VERSION 5.8 ;
BUSBITCHARS "[]" ;
DIVIDERCHAR "/" ;
UNITS
    DATABASE MICRONS 1000 ;
END UNITS

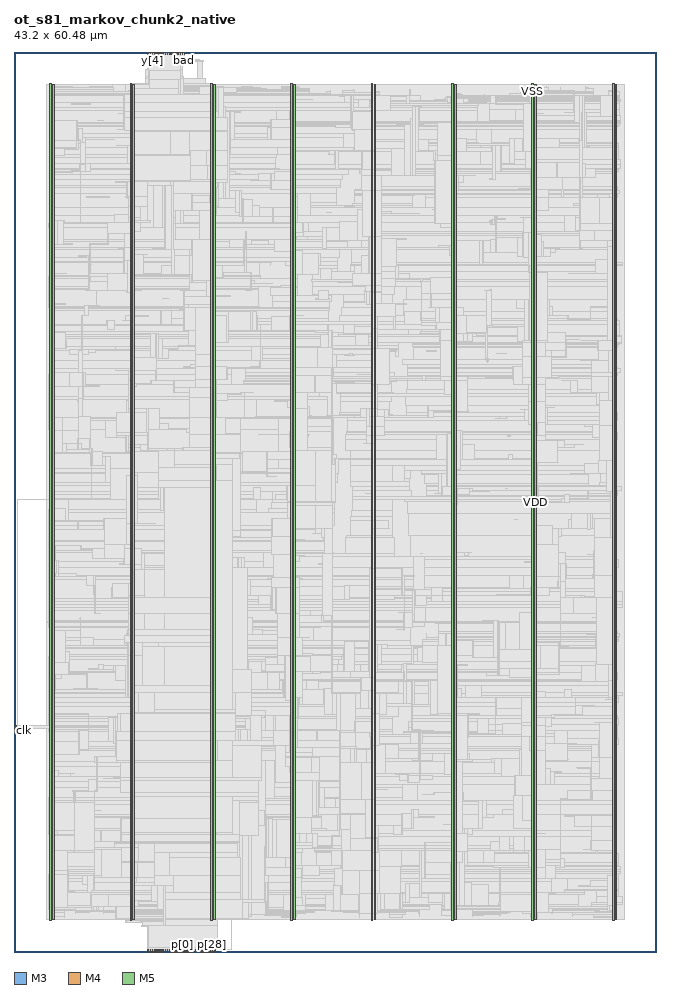
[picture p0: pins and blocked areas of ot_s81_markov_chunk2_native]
MACRO ot_s81_markov_chunk2_native
  FOREIGN ot_s81_markov_chunk2_native 0 0 ;
  CLASS BLOCK ;
  SIZE 43.2 BY 60.48 ;
  PIN bad
    DIRECTION OUTPUT ;
    USE SIGNAL ;
    PORT
      LAYER M3 ;
        RECT  11.448 60.336 11.466 60.48 ;
    END
  END bad
  PIN clk
    DIRECTION INPUT ;
    USE SIGNAL ;
    PORT
      LAYER M4 ;
        RECT  0 14.88 0.192 14.904 ;
    END
  END clk
  PIN p[0]
    DIRECTION INPUT ;
    USE SIGNAL ;
    PORT
      LAYER M3 ;
        RECT  11.304 0 11.322 0.144 ;
    END
  END p[0]
  PIN p[10]
    DIRECTION INPUT ;
    USE SIGNAL ;
    PORT
      LAYER M3 ;
        RECT  12.024 0 12.042 0.144 ;
    END
  END p[10]
  PIN p[11]
    DIRECTION INPUT ;
    USE SIGNAL ;
    PORT
      LAYER M5 ;
        RECT  12.048 0 12.072 0.192 ;
    END
  END p[11]
  PIN p[12]
    DIRECTION INPUT ;
    USE SIGNAL ;
    PORT
      LAYER M3 ;
        RECT  12.168 0 12.186 0.144 ;
    END
  END p[12]
  PIN p[13]
    DIRECTION INPUT ;
    USE SIGNAL ;
    PORT
      LAYER M5 ;
        RECT  12.192 0 12.216 0.192 ;
    END
  END p[13]
  PIN p[14]
    DIRECTION INPUT ;
    USE SIGNAL ;
    PORT
      LAYER M3 ;
        RECT  12.312 0 12.33 0.144 ;
    END
  END p[14]
  PIN p[15]
    DIRECTION INPUT ;
    USE SIGNAL ;
    PORT
      LAYER M5 ;
        RECT  12.336 0 12.36 0.192 ;
    END
  END p[15]
  PIN p[16]
    DIRECTION INPUT ;
    USE SIGNAL ;
    PORT
      LAYER M3 ;
        RECT  12.456 0 12.474 0.144 ;
    END
  END p[16]
  PIN p[17]
    DIRECTION INPUT ;
    USE SIGNAL ;
    PORT
      LAYER M5 ;
        RECT  12.48 0 12.504 0.192 ;
    END
  END p[17]
  PIN p[18]
    DIRECTION INPUT ;
    USE SIGNAL ;
    PORT
      LAYER M3 ;
        RECT  12.6 0 12.618 0.144 ;
    END
  END p[18]
  PIN p[19]
    DIRECTION INPUT ;
    USE SIGNAL ;
    PORT
      LAYER M5 ;
        RECT  12.624 0 12.648 0.192 ;
    END
  END p[19]
  PIN p[1]
    DIRECTION INPUT ;
    USE SIGNAL ;
    PORT
      LAYER M5 ;
        RECT  11.328 0 11.352 0.192 ;
    END
  END p[1]
  PIN p[20]
    DIRECTION INPUT ;
    USE SIGNAL ;
    PORT
      LAYER M3 ;
        RECT  12.744 0 12.762 0.144 ;
    END
  END p[20]
  PIN p[21]
    DIRECTION INPUT ;
    USE SIGNAL ;
    PORT
      LAYER M5 ;
        RECT  12.768 0 12.792 0.192 ;
    END
  END p[21]
  PIN p[22]
    DIRECTION INPUT ;
    USE SIGNAL ;
    PORT
      LAYER M3 ;
        RECT  12.888 0 12.906 0.144 ;
    END
  END p[22]
  PIN p[23]
    DIRECTION INPUT ;
    USE SIGNAL ;
    PORT
      LAYER M5 ;
        RECT  12.912 0 12.936 0.192 ;
    END
  END p[23]
  PIN p[24]
    DIRECTION INPUT ;
    USE SIGNAL ;
    PORT
      LAYER M3 ;
        RECT  13.032 0 13.05 0.144 ;
    END
  END p[24]
  PIN p[25]
    DIRECTION INPUT ;
    USE SIGNAL ;
    PORT
      LAYER M5 ;
        RECT  13.056 0 13.08 0.192 ;
    END
  END p[25]
  PIN p[26]
    DIRECTION INPUT ;
    USE SIGNAL ;
    PORT
      LAYER M3 ;
        RECT  13.176 0 13.194 0.144 ;
    END
  END p[26]
  PIN p[27]
    DIRECTION INPUT ;
    USE SIGNAL ;
    PORT
      LAYER M5 ;
        RECT  13.2 0 13.224 0.192 ;
    END
  END p[27]
  PIN p[28]
    DIRECTION INPUT ;
    USE SIGNAL ;
    PORT
      LAYER M3 ;
        RECT  13.32 0 13.338 0.144 ;
    END
  END p[28]
  PIN p[29]
    DIRECTION INPUT ;
    USE SIGNAL ;
    PORT
      LAYER M5 ;
        RECT  13.344 0 13.368 0.192 ;
    END
  END p[29]
  PIN p[2]
    DIRECTION INPUT ;
    USE SIGNAL ;
    PORT
      LAYER M3 ;
        RECT  11.448 0 11.466 0.144 ;
    END
  END p[2]
  PIN p[30]
    DIRECTION INPUT ;
    USE SIGNAL ;
    PORT
      LAYER M3 ;
        RECT  13.464 0 13.482 0.144 ;
    END
  END p[30]
  PIN p[31]
    DIRECTION INPUT ;
    USE SIGNAL ;
    PORT
      LAYER M5 ;
        RECT  13.488 0 13.512 0.192 ;
    END
  END p[31]
  PIN p[3]
    DIRECTION INPUT ;
    USE SIGNAL ;
    PORT
      LAYER M5 ;
        RECT  11.472 0 11.496 0.192 ;
    END
  END p[3]
  PIN p[4]
    DIRECTION INPUT ;
    USE SIGNAL ;
    PORT
      LAYER M3 ;
        RECT  11.592 0 11.61 0.144 ;
    END
  END p[4]
  PIN p[5]
    DIRECTION INPUT ;
    USE SIGNAL ;
    PORT
      LAYER M5 ;
        RECT  11.616 0 11.64 0.192 ;
    END
  END p[5]
  PIN p[6]
    DIRECTION INPUT ;
    USE SIGNAL ;
    PORT
      LAYER M3 ;
        RECT  11.736 0 11.754 0.144 ;
    END
  END p[6]
  PIN p[7]
    DIRECTION INPUT ;
    USE SIGNAL ;
    PORT
      LAYER M5 ;
        RECT  11.76 0 11.784 0.192 ;
    END
  END p[7]
  PIN p[8]
    DIRECTION INPUT ;
    USE SIGNAL ;
    PORT
      LAYER M3 ;
        RECT  11.88 0 11.898 0.144 ;
    END
  END p[8]
  PIN p[9]
    DIRECTION INPUT ;
    USE SIGNAL ;
    PORT
      LAYER M5 ;
        RECT  11.904 0 11.928 0.192 ;
    END
  END p[9]
  PIN rst_n
    DIRECTION INPUT ;
    USE SIGNAL ;
    PORT
      LAYER M4 ;
        RECT  0 15.024 0.192 15.048 ;
    END
  END rst_n
  PIN sum[0]
    DIRECTION INPUT ;
    USE SIGNAL ;
    PORT
      LAYER M3 ;
        RECT  9 0 9.018 0.144 ;
    END
  END sum[0]
  PIN sum[10]
    DIRECTION INPUT ;
    USE SIGNAL ;
    PORT
      LAYER M3 ;
        RECT  9.72 0 9.738 0.144 ;
    END
  END sum[10]
  PIN sum[11]
    DIRECTION INPUT ;
    USE SIGNAL ;
    PORT
      LAYER M5 ;
        RECT  9.744 0 9.768 0.192 ;
    END
  END sum[11]
  PIN sum[12]
    DIRECTION INPUT ;
    USE SIGNAL ;
    PORT
      LAYER M3 ;
        RECT  9.864 0 9.882 0.144 ;
    END
  END sum[12]
  PIN sum[13]
    DIRECTION INPUT ;
    USE SIGNAL ;
    PORT
      LAYER M5 ;
        RECT  9.888 0 9.912 0.192 ;
    END
  END sum[13]
  PIN sum[14]
    DIRECTION INPUT ;
    USE SIGNAL ;
    PORT
      LAYER M3 ;
        RECT  10.008 0 10.026 0.144 ;
    END
  END sum[14]
  PIN sum[15]
    DIRECTION INPUT ;
    USE SIGNAL ;
    PORT
      LAYER M5 ;
        RECT  10.032 0 10.056 0.192 ;
    END
  END sum[15]
  PIN sum[16]
    DIRECTION INPUT ;
    USE SIGNAL ;
    PORT
      LAYER M3 ;
        RECT  10.152 0 10.17 0.144 ;
    END
  END sum[16]
  PIN sum[17]
    DIRECTION INPUT ;
    USE SIGNAL ;
    PORT
      LAYER M5 ;
        RECT  10.176 0 10.2 0.192 ;
    END
  END sum[17]
  PIN sum[18]
    DIRECTION INPUT ;
    USE SIGNAL ;
    PORT
      LAYER M3 ;
        RECT  10.296 0 10.314 0.144 ;
    END
  END sum[18]
  PIN sum[19]
    DIRECTION INPUT ;
    USE SIGNAL ;
    PORT
      LAYER M5 ;
        RECT  10.32 0 10.344 0.192 ;
    END
  END sum[19]
  PIN sum[1]
    DIRECTION INPUT ;
    USE SIGNAL ;
    PORT
      LAYER M5 ;
        RECT  9.024 0 9.048 0.192 ;
    END
  END sum[1]
  PIN sum[20]
    DIRECTION INPUT ;
    USE SIGNAL ;
    PORT
      LAYER M3 ;
        RECT  10.44 0 10.458 0.144 ;
    END
  END sum[20]
  PIN sum[21]
    DIRECTION INPUT ;
    USE SIGNAL ;
    PORT
      LAYER M5 ;
        RECT  10.464 0 10.488 0.192 ;
    END
  END sum[21]
  PIN sum[22]
    DIRECTION INPUT ;
    USE SIGNAL ;
    PORT
      LAYER M3 ;
        RECT  10.584 0 10.602 0.144 ;
    END
  END sum[22]
  PIN sum[23]
    DIRECTION INPUT ;
    USE SIGNAL ;
    PORT
      LAYER M5 ;
        RECT  10.608 0 10.632 0.192 ;
    END
  END sum[23]
  PIN sum[24]
    DIRECTION INPUT ;
    USE SIGNAL ;
    PORT
      LAYER M3 ;
        RECT  10.728 0 10.746 0.144 ;
    END
  END sum[24]
  PIN sum[25]
    DIRECTION INPUT ;
    USE SIGNAL ;
    PORT
      LAYER M5 ;
        RECT  10.752 0 10.776 0.192 ;
    END
  END sum[25]
  PIN sum[26]
    DIRECTION INPUT ;
    USE SIGNAL ;
    PORT
      LAYER M3 ;
        RECT  10.872 0 10.89 0.144 ;
    END
  END sum[26]
  PIN sum[27]
    DIRECTION INPUT ;
    USE SIGNAL ;
    PORT
      LAYER M5 ;
        RECT  10.896 0 10.92 0.192 ;
    END
  END sum[27]
  PIN sum[28]
    DIRECTION INPUT ;
    USE SIGNAL ;
    PORT
      LAYER M3 ;
        RECT  11.016 0 11.034 0.144 ;
    END
  END sum[28]
  PIN sum[29]
    DIRECTION INPUT ;
    USE SIGNAL ;
    PORT
      LAYER M5 ;
        RECT  11.04 0 11.064 0.192 ;
    END
  END sum[29]
  PIN sum[2]
    DIRECTION INPUT ;
    USE SIGNAL ;
    PORT
      LAYER M3 ;
        RECT  9.144 0 9.162 0.144 ;
    END
  END sum[2]
  PIN sum[30]
    DIRECTION INPUT ;
    USE SIGNAL ;
    PORT
      LAYER M3 ;
        RECT  11.16 0 11.178 0.144 ;
    END
  END sum[30]
  PIN sum[31]
    DIRECTION INPUT ;
    USE SIGNAL ;
    PORT
      LAYER M5 ;
        RECT  11.184 0 11.208 0.192 ;
    END
  END sum[31]
  PIN sum[3]
    DIRECTION INPUT ;
    USE SIGNAL ;
    PORT
      LAYER M5 ;
        RECT  9.168 0 9.192 0.192 ;
    END
  END sum[3]
  PIN sum[4]
    DIRECTION INPUT ;
    USE SIGNAL ;
    PORT
      LAYER M3 ;
        RECT  9.288 0 9.306 0.144 ;
    END
  END sum[4]
  PIN sum[5]
    DIRECTION INPUT ;
    USE SIGNAL ;
    PORT
      LAYER M5 ;
        RECT  9.312 0 9.336 0.192 ;
    END
  END sum[5]
  PIN sum[6]
    DIRECTION INPUT ;
    USE SIGNAL ;
    PORT
      LAYER M3 ;
        RECT  9.432 0 9.45 0.144 ;
    END
  END sum[6]
  PIN sum[7]
    DIRECTION INPUT ;
    USE SIGNAL ;
    PORT
      LAYER M5 ;
        RECT  9.456 0 9.48 0.192 ;
    END
  END sum[7]
  PIN sum[8]
    DIRECTION INPUT ;
    USE SIGNAL ;
    PORT
      LAYER M3 ;
        RECT  9.576 0 9.594 0.144 ;
    END
  END sum[8]
  PIN sum[9]
    DIRECTION INPUT ;
    USE SIGNAL ;
    PORT
      LAYER M5 ;
        RECT  9.6 0 9.624 0.192 ;
    END
  END sum[9]
  PIN vin
    DIRECTION INPUT ;
    USE SIGNAL ;
    PORT
      LAYER M4 ;
        RECT  0 15.168 0.192 15.192 ;
    END
  END vin
  PIN vout
    DIRECTION OUTPUT ;
    USE SIGNAL ;
    PORT
      LAYER M3 ;
        RECT  11.304 60.336 11.322 60.48 ;
    END
  END vout
  PIN y[0]
    DIRECTION OUTPUT ;
    USE SIGNAL ;
    PORT
      LAYER M3 ;
        RECT  9 60.336 9.018 60.48 ;
    END
  END y[0]
  PIN y[10]
    DIRECTION OUTPUT ;
    USE SIGNAL ;
    PORT
      LAYER M3 ;
        RECT  9.72 60.336 9.738 60.48 ;
    END
  END y[10]
  PIN y[11]
    DIRECTION OUTPUT ;
    USE SIGNAL ;
    PORT
      LAYER M5 ;
        RECT  9.744 60.288 9.768 60.48 ;
    END
  END y[11]
  PIN y[12]
    DIRECTION OUTPUT ;
    USE SIGNAL ;
    PORT
      LAYER M3 ;
        RECT  9.864 60.336 9.882 60.48 ;
    END
  END y[12]
  PIN y[13]
    DIRECTION OUTPUT ;
    USE SIGNAL ;
    PORT
      LAYER M5 ;
        RECT  9.888 60.288 9.912 60.48 ;
    END
  END y[13]
  PIN y[14]
    DIRECTION OUTPUT ;
    USE SIGNAL ;
    PORT
      LAYER M3 ;
        RECT  10.008 60.336 10.026 60.48 ;
    END
  END y[14]
  PIN y[15]
    DIRECTION OUTPUT ;
    USE SIGNAL ;
    PORT
      LAYER M5 ;
        RECT  10.032 60.288 10.056 60.48 ;
    END
  END y[15]
  PIN y[16]
    DIRECTION OUTPUT ;
    USE SIGNAL ;
    PORT
      LAYER M3 ;
        RECT  10.152 60.336 10.17 60.48 ;
    END
  END y[16]
  PIN y[17]
    DIRECTION OUTPUT ;
    USE SIGNAL ;
    PORT
      LAYER M5 ;
        RECT  10.176 60.288 10.2 60.48 ;
    END
  END y[17]
  PIN y[18]
    DIRECTION OUTPUT ;
    USE SIGNAL ;
    PORT
      LAYER M3 ;
        RECT  10.296 60.336 10.314 60.48 ;
    END
  END y[18]
  PIN y[19]
    DIRECTION OUTPUT ;
    USE SIGNAL ;
    PORT
      LAYER M5 ;
        RECT  10.32 60.288 10.344 60.48 ;
    END
  END y[19]
  PIN y[1]
    DIRECTION OUTPUT ;
    USE SIGNAL ;
    PORT
      LAYER M5 ;
        RECT  9.024 60.288 9.048 60.48 ;
    END
  END y[1]
  PIN y[20]
    DIRECTION OUTPUT ;
    USE SIGNAL ;
    PORT
      LAYER M3 ;
        RECT  10.44 60.336 10.458 60.48 ;
    END
  END y[20]
  PIN y[21]
    DIRECTION OUTPUT ;
    USE SIGNAL ;
    PORT
      LAYER M5 ;
        RECT  10.464 60.288 10.488 60.48 ;
    END
  END y[21]
  PIN y[22]
    DIRECTION OUTPUT ;
    USE SIGNAL ;
    PORT
      LAYER M3 ;
        RECT  10.584 60.336 10.602 60.48 ;
    END
  END y[22]
  PIN y[23]
    DIRECTION OUTPUT ;
    USE SIGNAL ;
    PORT
      LAYER M5 ;
        RECT  10.608 60.288 10.632 60.48 ;
    END
  END y[23]
  PIN y[24]
    DIRECTION OUTPUT ;
    USE SIGNAL ;
    PORT
      LAYER M3 ;
        RECT  10.728 60.336 10.746 60.48 ;
    END
  END y[24]
  PIN y[25]
    DIRECTION OUTPUT ;
    USE SIGNAL ;
    PORT
      LAYER M5 ;
        RECT  10.752 60.288 10.776 60.48 ;
    END
  END y[25]
  PIN y[26]
    DIRECTION OUTPUT ;
    USE SIGNAL ;
    PORT
      LAYER M3 ;
        RECT  10.872 60.336 10.89 60.48 ;
    END
  END y[26]
  PIN y[27]
    DIRECTION OUTPUT ;
    USE SIGNAL ;
    PORT
      LAYER M5 ;
        RECT  10.896 60.288 10.92 60.48 ;
    END
  END y[27]
  PIN y[28]
    DIRECTION OUTPUT ;
    USE SIGNAL ;
    PORT
      LAYER M3 ;
        RECT  11.016 60.336 11.034 60.48 ;
    END
  END y[28]
  PIN y[29]
    DIRECTION OUTPUT ;
    USE SIGNAL ;
    PORT
      LAYER M5 ;
        RECT  11.04 60.288 11.064 60.48 ;
    END
  END y[29]
  PIN y[2]
    DIRECTION OUTPUT ;
    USE SIGNAL ;
    PORT
      LAYER M3 ;
        RECT  9.144 60.336 9.162 60.48 ;
    END
  END y[2]
  PIN y[30]
    DIRECTION OUTPUT ;
    USE SIGNAL ;
    PORT
      LAYER M3 ;
        RECT  11.16 60.336 11.178 60.48 ;
    END
  END y[30]
  PIN y[31]
    DIRECTION OUTPUT ;
    USE SIGNAL ;
    PORT
      LAYER M5 ;
        RECT  11.184 60.288 11.208 60.48 ;
    END
  END y[31]
  PIN y[3]
    DIRECTION OUTPUT ;
    USE SIGNAL ;
    PORT
      LAYER M5 ;
        RECT  9.168 60.288 9.192 60.48 ;
    END
  END y[3]
  PIN y[4]
    DIRECTION OUTPUT ;
    USE SIGNAL ;
    PORT
      LAYER M3 ;
        RECT  9.288 60.336 9.306 60.48 ;
    END
  END y[4]
  PIN y[5]
    DIRECTION OUTPUT ;
    USE SIGNAL ;
    PORT
      LAYER M5 ;
        RECT  9.312 60.288 9.336 60.48 ;
    END
  END y[5]
  PIN y[6]
    DIRECTION OUTPUT ;
    USE SIGNAL ;
    PORT
      LAYER M3 ;
        RECT  9.432 60.336 9.45 60.48 ;
    END
  END y[6]
  PIN y[7]
    DIRECTION OUTPUT ;
    USE SIGNAL ;
    PORT
      LAYER M5 ;
        RECT  9.456 60.288 9.48 60.48 ;
    END
  END y[7]
  PIN y[8]
    DIRECTION OUTPUT ;
    USE SIGNAL ;
    PORT
      LAYER M3 ;
        RECT  9.576 60.336 9.594 60.48 ;
    END
  END y[8]
  PIN y[9]
    DIRECTION OUTPUT ;
    USE SIGNAL ;
    PORT
      LAYER M5 ;
        RECT  9.6 60.288 9.624 60.48 ;
    END
  END y[9]
  PIN VDD
    DIRECTION INOUT ;
    USE POWER ;
    PORT
      LAYER M5 ;
        RECT  40.392 2.151 40.512 58.329 ;
        RECT  34.992 2.151 35.112 58.329 ;
        RECT  29.592 2.151 29.712 58.329 ;
        RECT  24.192 2.151 24.312 58.329 ;
        RECT  18.792 2.151 18.912 58.329 ;
        RECT  13.392 2.151 13.512 58.329 ;
        RECT  7.992 2.151 8.112 58.329 ;
        RECT  2.592 2.151 2.712 58.329 ;
    END
  END VDD
  PIN VSS
    DIRECTION INOUT ;
    USE GROUND ;
    PORT
      LAYER M5 ;
        RECT  40.2 2.137 40.32 58.343 ;
        RECT  34.8 2.137 34.92 58.343 ;
        RECT  29.4 2.137 29.52 58.343 ;
        RECT  24 2.137 24.12 58.343 ;
        RECT  18.6 2.137 18.72 58.343 ;
        RECT  13.2 2.137 13.32 58.343 ;
        RECT  7.8 2.137 7.92 58.343 ;
        RECT  2.4 2.137 2.52 58.343 ;
    END
  END VSS
  # OT_OBS_CLOSED layer=M5 d_um=1.536 added=207
  OBS
    LAYER RVTN ;
     RECT  2.16 2.16 41.04 2.295 ;
     RECT  2.16 2.565 41.04 2.835 ;
     RECT  2.16 3.105 41.04 3.375 ;
     RECT  2.16 3.645 41.04 3.915 ;
     RECT  2.16 4.185 41.04 4.455 ;
     RECT  2.16 4.725 41.04 4.995 ;
     RECT  2.16 5.265 41.04 5.535 ;
     RECT  2.16 5.805 41.04 6.075 ;
     RECT  2.16 6.345 41.04 6.615 ;
     RECT  2.16 6.885 41.04 7.155 ;
     RECT  2.16 7.425 41.04 7.695 ;
     RECT  2.16 7.965 41.04 8.235 ;
     RECT  2.16 8.505 41.04 8.775 ;
     RECT  2.16 9.045 41.04 9.315 ;
     RECT  2.16 9.585 41.04 9.855 ;
     RECT  2.16 10.125 41.04 10.395 ;
     RECT  2.16 10.665 41.04 10.935 ;
     RECT  2.16 11.205 41.04 11.475 ;
     RECT  2.16 11.745 41.04 12.015 ;
     RECT  2.16 12.285 41.04 12.555 ;
     RECT  2.16 12.825 41.04 13.095 ;
     RECT  2.16 13.365 41.04 13.635 ;
     RECT  2.16 13.905 41.04 14.175 ;
     RECT  2.16 14.445 41.04 14.715 ;
     RECT  2.16 14.985 41.04 15.255 ;
     RECT  2.16 15.525 41.04 15.795 ;
     RECT  2.16 16.065 41.04 16.335 ;
     RECT  2.16 16.605 41.04 16.875 ;
     RECT  2.16 17.145 41.04 17.415 ;
     RECT  2.16 17.685 41.04 17.955 ;
     RECT  2.16 18.225 41.04 18.495 ;
     RECT  2.16 18.765 41.04 19.035 ;
     RECT  2.16 19.305 41.04 19.575 ;
     RECT  2.16 19.845 41.04 20.115 ;
     RECT  2.16 20.385 41.04 20.655 ;
     RECT  2.16 20.925 41.04 21.195 ;
     RECT  2.16 21.465 41.04 21.735 ;
     RECT  2.16 22.005 41.04 22.275 ;
     RECT  2.16 22.545 41.04 22.815 ;
     RECT  2.16 23.085 41.04 23.355 ;
     RECT  2.16 23.625 41.04 23.895 ;
     RECT  2.16 24.165 41.04 24.435 ;
     RECT  2.16 24.705 41.04 24.975 ;
     RECT  2.16 25.245 41.04 25.515 ;
     RECT  2.16 25.785 41.04 26.055 ;
     RECT  2.16 26.325 41.04 26.595 ;
     RECT  2.16 26.865 41.04 27.135 ;
     RECT  2.16 27.405 41.04 27.675 ;
     RECT  2.16 27.945 41.04 28.215 ;
     RECT  2.16 28.485 41.04 28.755 ;
     RECT  2.16 29.025 41.04 29.295 ;
     RECT  2.16 29.565 41.04 29.835 ;
     RECT  2.16 30.105 41.04 30.375 ;
     RECT  2.16 30.645 41.04 30.915 ;
     RECT  2.16 31.185 41.04 31.455 ;
     RECT  2.16 31.725 41.04 31.995 ;
     RECT  2.16 32.265 41.04 32.535 ;
     RECT  2.16 32.805 41.04 33.075 ;
     RECT  2.16 33.345 41.04 33.615 ;
     RECT  2.16 33.885 41.04 34.155 ;
     RECT  2.16 34.425 41.04 34.695 ;
     RECT  2.16 34.965 41.04 35.235 ;
     RECT  2.16 35.505 41.04 35.775 ;
     RECT  2.16 36.045 41.04 36.315 ;
     RECT  2.16 36.585 41.04 36.855 ;
     RECT  2.16 37.125 41.04 37.395 ;
     RECT  2.16 37.665 41.04 37.935 ;
     RECT  2.16 38.205 41.04 38.475 ;
     RECT  2.16 38.745 41.04 39.015 ;
     RECT  2.16 39.285 41.04 39.555 ;
     RECT  2.16 39.825 41.04 40.095 ;
     RECT  2.16 40.365 41.04 40.635 ;
     RECT  2.16 40.905 41.04 41.175 ;
     RECT  2.16 41.445 41.04 41.715 ;
     RECT  2.16 41.985 41.04 42.255 ;
     RECT  2.16 42.525 41.04 42.795 ;
     RECT  2.16 43.065 41.04 43.335 ;
     RECT  2.16 43.605 41.04 43.875 ;
     RECT  2.16 44.145 41.04 44.415 ;
     RECT  2.16 44.685 41.04 44.955 ;
     RECT  2.16 45.225 41.04 45.495 ;
     RECT  2.16 45.765 41.04 46.035 ;
     RECT  2.16 46.305 41.04 46.575 ;
     RECT  2.16 46.845 41.04 47.115 ;
     RECT  2.16 47.385 41.04 47.655 ;
     RECT  2.16 47.925 41.04 48.195 ;
     RECT  2.16 48.465 41.04 48.735 ;
     RECT  2.16 49.005 41.04 49.275 ;
     RECT  2.16 49.545 41.04 49.815 ;
     RECT  2.16 50.085 41.04 50.355 ;
     RECT  2.16 50.625 41.04 50.895 ;
     RECT  2.16 51.165 41.04 51.435 ;
     RECT  2.16 51.705 41.04 51.975 ;
     RECT  2.16 52.245 41.04 52.515 ;
     RECT  2.16 52.785 41.04 53.055 ;
     RECT  2.16 53.325 41.04 53.595 ;
     RECT  2.16 53.865 41.04 54.135 ;
     RECT  2.16 54.405 41.04 54.675 ;
     RECT  2.16 54.945 41.04 55.215 ;
     RECT  2.16 55.485 41.04 55.755 ;
     RECT  2.16 56.025 41.04 56.295 ;
     RECT  2.16 56.565 41.04 56.835 ;
     RECT  2.16 57.105 41.04 57.375 ;
     RECT  2.16 57.645 41.04 57.915 ;
     RECT  2.16 58.185 41.04 58.32 ;
    LAYER RVTP ;
     RECT  2.16 2.295 41.04 2.565 ;
     RECT  2.16 2.835 41.04 3.105 ;
     RECT  2.16 3.375 41.04 3.645 ;
     RECT  2.16 3.915 41.04 4.185 ;
     RECT  2.16 4.455 41.04 4.725 ;
     RECT  2.16 4.995 41.04 5.265 ;
     RECT  2.16 5.535 41.04 5.805 ;
     RECT  2.16 6.075 41.04 6.345 ;
     RECT  2.16 6.615 41.04 6.885 ;
     RECT  2.16 7.155 41.04 7.425 ;
     RECT  2.16 7.695 41.04 7.965 ;
     RECT  2.16 8.235 41.04 8.505 ;
     RECT  2.16 8.775 41.04 9.045 ;
     RECT  2.16 9.315 41.04 9.585 ;
     RECT  2.16 9.855 41.04 10.125 ;
     RECT  2.16 10.395 41.04 10.665 ;
     RECT  2.16 10.935 41.04 11.205 ;
     RECT  2.16 11.475 41.04 11.745 ;
     RECT  2.16 12.015 41.04 12.285 ;
     RECT  2.16 12.555 41.04 12.825 ;
     RECT  2.16 13.095 41.04 13.365 ;
     RECT  2.16 13.635 41.04 13.905 ;
     RECT  2.16 14.175 41.04 14.445 ;
     RECT  2.16 14.715 41.04 14.985 ;
     RECT  2.16 15.255 41.04 15.525 ;
     RECT  2.16 15.795 41.04 16.065 ;
     RECT  2.16 16.335 41.04 16.605 ;
     RECT  2.16 16.875 41.04 17.145 ;
     RECT  2.16 17.415 41.04 17.685 ;
     RECT  2.16 17.955 41.04 18.225 ;
     RECT  2.16 18.495 41.04 18.765 ;
     RECT  2.16 19.035 41.04 19.305 ;
     RECT  2.16 19.575 41.04 19.845 ;
     RECT  2.16 20.115 41.04 20.385 ;
     RECT  2.16 20.655 41.04 20.925 ;
     RECT  2.16 21.195 41.04 21.465 ;
     RECT  2.16 21.735 41.04 22.005 ;
     RECT  2.16 22.275 41.04 22.545 ;
     RECT  2.16 22.815 41.04 23.085 ;
     RECT  2.16 23.355 41.04 23.625 ;
     RECT  2.16 23.895 41.04 24.165 ;
     RECT  2.16 24.435 41.04 24.705 ;
     RECT  2.16 24.975 41.04 25.245 ;
     RECT  2.16 25.515 41.04 25.785 ;
     RECT  2.16 26.055 41.04 26.325 ;
     RECT  2.16 26.595 41.04 26.865 ;
     RECT  2.16 27.135 41.04 27.405 ;
     RECT  2.16 27.675 41.04 27.945 ;
     RECT  2.16 28.215 41.04 28.485 ;
     RECT  2.16 28.755 41.04 29.025 ;
     RECT  2.16 29.295 41.04 29.565 ;
     RECT  2.16 29.835 41.04 30.105 ;
     RECT  2.16 30.375 41.04 30.645 ;
     RECT  2.16 30.915 41.04 31.185 ;
     RECT  2.16 31.455 41.04 31.725 ;
     RECT  2.16 31.995 41.04 32.265 ;
     RECT  2.16 32.535 41.04 32.805 ;
     RECT  2.16 33.075 41.04 33.345 ;
     RECT  2.16 33.615 41.04 33.885 ;
     RECT  2.16 34.155 41.04 34.425 ;
     RECT  2.16 34.695 41.04 34.965 ;
     RECT  2.16 35.235 41.04 35.505 ;
     RECT  2.16 35.775 41.04 36.045 ;
     RECT  2.16 36.315 41.04 36.585 ;
     RECT  2.16 36.855 41.04 37.125 ;
     RECT  2.16 37.395 41.04 37.665 ;
     RECT  2.16 37.935 41.04 38.205 ;
     RECT  2.16 38.475 41.04 38.745 ;
     RECT  2.16 39.015 41.04 39.285 ;
     RECT  2.16 39.555 41.04 39.825 ;
     RECT  2.16 40.095 41.04 40.365 ;
     RECT  2.16 40.635 41.04 40.905 ;
     RECT  2.16 41.175 41.04 41.445 ;
     RECT  2.16 41.715 41.04 41.985 ;
     RECT  2.16 42.255 41.04 42.525 ;
     RECT  2.16 42.795 41.04 43.065 ;
     RECT  2.16 43.335 41.04 43.605 ;
     RECT  2.16 43.875 41.04 44.145 ;
     RECT  2.16 44.415 41.04 44.685 ;
     RECT  2.16 44.955 41.04 45.225 ;
     RECT  2.16 45.495 41.04 45.765 ;
     RECT  2.16 46.035 41.04 46.305 ;
     RECT  2.16 46.575 41.04 46.845 ;
     RECT  2.16 47.115 41.04 47.385 ;
     RECT  2.16 47.655 41.04 47.925 ;
     RECT  2.16 48.195 41.04 48.465 ;
     RECT  2.16 48.735 41.04 49.005 ;
     RECT  2.16 49.275 41.04 49.545 ;
     RECT  2.16 49.815 41.04 50.085 ;
     RECT  2.16 50.355 41.04 50.625 ;
     RECT  2.16 50.895 41.04 51.165 ;
     RECT  2.16 51.435 41.04 51.705 ;
     RECT  2.16 51.975 41.04 52.245 ;
     RECT  2.16 52.515 41.04 52.785 ;
     RECT  2.16 53.055 41.04 53.325 ;
     RECT  2.16 53.595 41.04 53.865 ;
     RECT  2.16 54.135 41.04 54.405 ;
     RECT  2.16 54.675 41.04 54.945 ;
     RECT  2.16 55.215 41.04 55.485 ;
     RECT  2.16 55.755 41.04 56.025 ;
     RECT  2.16 56.295 41.04 56.565 ;
     RECT  2.16 56.835 41.04 57.105 ;
     RECT  2.16 57.375 41.04 57.645 ;
     RECT  2.16 57.915 41.04 58.185 ;
    LAYER M1 ;
     RECT  2.16 2.151 41.04 58.329 ;
    LAYER M2 ;
     RECT  2.16 2.151 7.519 58.329 ;
     RECT  7.519 1.998 8.887 58.329 ;
     RECT  8.887 1.998 9.023 58.716 ;
     RECT  9.023 1.998 9.131 58.329 ;
     RECT  9.131 2.07 9.167 58.329 ;
     RECT  9.211 0.144 9.311 0.162 ;
     RECT  9.167 2.106 9.751 58.329 ;
     RECT  9.751 2.106 9.887 58.869 ;
     RECT  10.255 0.216 10.291 0.234 ;
     RECT  9.887 2.106 10.579 58.824 ;
     RECT  10.291 0.144 10.751 0.234 ;
     RECT  10.723 59.85 10.867 59.868 ;
     RECT  10.579 1.728 11.219 58.824 ;
     RECT  10.751 0.144 11.363 0.162 ;
     RECT  11.219 2.151 11.363 58.824 ;
     RECT  11.587 0.216 12.163 0.234 ;
     RECT  10.867 59.85 12.335 59.949 ;
     RECT  12.163 0.144 12.371 0.234 ;
     RECT  12.335 59.931 12.479 59.949 ;
     RECT  11.363 2.151 12.875 58.716 ;
     RECT  12.371 0.144 14.639 0.162 ;
     RECT  12.875 2.151 41.04 58.329 ;
    LAYER M3 ;
     RECT  9 0.108 13.482 0.317 ;
     RECT  9 0.317 13.194 1.723 ;
     RECT  8.604 1.723 13.554 2.065 ;
     RECT  7.524 1.993 7.542 2.101 ;
     RECT  8.532 2.065 13.554 2.101 ;
     RECT  7.524 2.101 13.554 2.191 ;
     RECT  14.616 0.139 14.634 2.191 ;
     RECT  34.815 2.143 34.905 2.227 ;
     RECT  7.524 2.191 15.318 2.251 ;
     RECT  34.815 2.227 35.154 2.299 ;
     RECT  40.215 2.143 40.305 2.299 ;
     RECT  18.615 2.143 18.705 2.335 ;
     RECT  34.704 2.299 35.154 2.335 ;
     RECT  3.384 2.335 3.402 2.371 ;
     RECT  6.876 2.251 15.75 2.371 ;
     RECT  18 2.335 18.705 2.371 ;
     RECT  2.415 2.143 2.505 2.413 ;
     RECT  3.24 2.371 3.402 2.413 ;
     RECT  24.015 2.143 24.105 2.413 ;
     RECT  29.415 2.143 29.505 2.413 ;
     RECT  38.952 2.299 40.305 2.413 ;
     RECT  18 2.371 18.954 2.461 ;
     RECT  29.415 2.413 29.697 2.461 ;
     RECT  30.78 2.371 30.798 2.461 ;
     RECT  25.236 2.335 26.118 2.533 ;
     RECT  30.78 2.461 31.518 2.533 ;
     RECT  32.652 2.461 32.67 2.533 ;
     RECT  37.512 2.371 37.53 2.533 ;
     RECT  38.952 2.413 40.497 2.533 ;
     RECT  6.84 2.371 15.93 2.539 ;
     RECT  16.848 2.461 18.954 2.539 ;
     RECT  30.78 2.533 32.67 2.569 ;
     RECT  6.84 2.539 18.954 2.605 ;
     RECT  27.252 2.371 27.27 2.605 ;
     RECT  34.704 2.335 35.19 2.605 ;
     RECT  2.415 2.413 3.402 2.641 ;
     RECT  4.14 2.605 4.158 2.641 ;
     RECT  6.012 2.605 6.03 2.641 ;
     RECT  6.84 2.605 19.602 2.641 ;
     RECT  23.184 2.335 23.202 2.641 ;
     RECT  24.015 2.413 24.297 2.641 ;
     RECT  25.236 2.533 26.334 2.641 ;
     RECT  30.78 2.569 33.138 2.641 ;
     RECT  36.144 2.605 36.162 2.641 ;
     RECT  37.512 2.533 40.497 2.641 ;
     RECT  4.14 2.641 5.094 2.731 ;
     RECT  6.012 2.641 20.178 2.731 ;
     RECT  22.14 2.641 23.202 2.731 ;
     RECT  24.015 2.641 26.334 2.731 ;
     RECT  27.18 2.605 27.27 2.731 ;
     RECT  30.78 2.641 33.354 2.731 ;
     RECT  34.2 2.605 35.19 2.731 ;
     RECT  2.376 2.641 3.402 2.767 ;
     RECT  4.14 2.731 20.178 2.767 ;
     RECT  21.312 2.731 27.27 2.767 ;
     RECT  28.728 2.461 29.697 2.767 ;
     RECT  36.144 2.641 40.497 2.767 ;
     RECT  2.376 2.767 27.27 2.861 ;
     RECT  4.608 2.861 27.27 2.875 ;
     RECT  28.728 2.767 29.754 2.875 ;
     RECT  30.78 2.731 35.19 2.875 ;
     RECT  36 2.767 40.497 2.875 ;
     RECT  2.376 2.861 3.834 2.909 ;
     RECT  28.728 2.875 35.19 2.911 ;
     RECT  35.964 2.875 40.497 2.911 ;
     RECT  4.608 2.875 27.918 3.029 ;
     RECT  28.728 2.911 40.497 3.029 ;
     RECT  4.824 3.029 27.918 3.145 ;
     RECT  4.824 3.145 27.954 3.149 ;
     RECT  4.932 3.149 27.954 3.181 ;
     RECT  28.728 3.029 37.962 3.181 ;
     RECT  38.808 3.029 40.497 3.181 ;
     RECT  38.808 3.181 40.914 3.335 ;
     RECT  39.168 3.335 40.914 3.713 ;
     RECT  4.932 3.181 37.962 3.847 ;
     RECT  2.415 2.909 3.834 3.931 ;
     RECT  4.932 3.847 38.322 3.965 ;
     RECT  2.34 3.931 3.834 3.983 ;
     RECT  25.164 3.965 38.322 3.983 ;
     RECT  2.415 3.983 3.834 4.081 ;
     RECT  2.415 4.081 4.05 4.153 ;
     RECT  4.932 3.965 24.39 4.153 ;
     RECT  36.972 3.983 38.322 4.153 ;
     RECT  39.168 3.713 40.626 4.153 ;
     RECT  36.972 4.153 40.626 4.181 ;
     RECT  2.415 4.153 24.39 4.729 ;
     RECT  25.164 3.983 36.126 4.729 ;
     RECT  2.415 4.729 36.126 4.927 ;
     RECT  37.188 4.181 40.626 4.927 ;
     RECT  2.415 4.927 40.626 5.305 ;
     RECT  2.415 5.305 40.734 5.431 ;
     RECT  2.376 5.431 40.734 5.531 ;
     RECT  2.415 5.531 40.734 5.729 ;
     RECT  2.415 5.729 40.626 5.765 ;
     RECT  20.052 5.765 40.626 5.801 ;
     RECT  20.052 5.801 21.402 5.837 ;
     RECT  22.14 5.801 40.626 5.999 ;
     RECT  32.256 5.999 40.626 6.611 ;
     RECT  2.415 5.765 19.314 6.691 ;
     RECT  20.34 5.837 21.366 6.691 ;
     RECT  32.256 6.611 40.497 6.719 ;
     RECT  20.268 6.691 21.366 6.781 ;
     RECT  20.16 6.781 21.366 6.817 ;
     RECT  22.14 5.999 31.518 6.817 ;
     RECT  20.16 6.817 31.518 6.853 ;
     RECT  32.256 6.719 33.534 6.853 ;
     RECT  2.415 6.691 19.386 6.961 ;
     RECT  20.16 6.853 33.534 6.961 ;
     RECT  2.376 6.961 33.534 7.187 ;
     RECT  2.415 7.187 33.534 7.771 ;
     RECT  34.272 6.719 40.497 7.771 ;
     RECT  2.415 7.771 40.497 8.159 ;
     RECT  2.415 8.159 21.006 8.195 ;
     RECT  2.415 8.195 20.97 8.267 ;
     RECT  2.415 8.267 20.646 9.067 ;
     RECT  2.34 9.067 20.646 9.113 ;
     RECT  2.415 9.113 20.646 9.247 ;
     RECT  21.744 8.159 40.497 9.247 ;
     RECT  2.415 9.247 40.497 9.931 ;
     RECT  2.34 9.931 40.497 10.157 ;
     RECT  2.34 10.157 26.118 10.193 ;
     RECT  2.34 10.193 26.082 10.355 ;
     RECT  2.415 10.355 26.082 11.039 ;
     RECT  24.015 11.039 26.082 11.281 ;
     RECT  27.108 10.157 40.497 11.281 ;
     RECT  2.415 11.039 23.166 11.453 ;
     RECT  2.415 11.453 17.082 11.785 ;
     RECT  17.856 11.453 23.166 11.821 ;
     RECT  24.015 11.281 40.497 11.821 ;
     RECT  17.856 11.821 40.497 11.975 ;
     RECT  2.376 11.785 17.082 12.475 ;
     RECT  17.856 11.975 20.826 12.475 ;
     RECT  2.376 12.475 20.826 12.793 ;
     RECT  21.564 11.975 40.497 12.793 ;
     RECT  2.376 12.793 40.497 13.559 ;
     RECT  2.415 13.559 40.497 13.667 ;
     RECT  2.415 13.667 23.022 13.829 ;
     RECT  30.492 13.667 40.497 13.829 ;
     RECT  37.224 13.829 40.497 13.945 ;
     RECT  23.94 13.667 29.697 13.997 ;
     RECT  37.224 13.945 40.626 14.369 ;
     RECT  23.94 13.997 26.622 14.449 ;
     RECT  27.468 13.997 29.697 14.449 ;
     RECT  30.492 13.829 36.306 14.449 ;
     RECT  23.904 14.449 26.622 14.639 ;
     RECT  27.468 14.449 36.306 14.675 ;
     RECT  26.172 14.639 26.622 14.755 ;
     RECT  27.468 14.675 31.122 14.755 ;
     RECT  2.415 13.829 22.95 14.791 ;
     RECT  23.904 14.639 25.434 14.791 ;
     RECT  26.172 14.755 31.122 14.819 ;
     RECT  31.896 14.675 36.306 14.881 ;
     RECT  37.224 14.369 40.554 14.881 ;
     RECT  2.34 14.791 25.434 14.957 ;
     RECT  2.34 14.957 15.534 15.061 ;
     RECT  2.304 15.061 15.534 15.163 ;
     RECT  2.268 15.163 15.534 15.215 ;
     RECT  31.896 14.881 40.554 15.259 ;
     RECT  2.304 15.215 15.534 15.485 ;
     RECT  26.532 14.819 31.122 15.485 ;
     RECT  2.34 15.485 15.534 15.691 ;
     RECT  16.704 14.957 25.434 15.691 ;
     RECT  26.712 15.485 31.122 15.691 ;
     RECT  31.896 15.259 40.59 15.691 ;
     RECT  26.712 15.691 40.59 15.719 ;
     RECT  2.34 15.691 25.434 15.799 ;
     RECT  26.712 15.719 40.554 15.863 ;
     RECT  2.34 15.799 25.83 16.501 ;
     RECT  26.712 15.863 40.497 16.501 ;
     RECT  2.34 16.501 40.497 16.771 ;
     RECT  2.34 16.771 40.626 17.117 ;
     RECT  31.392 17.117 40.626 17.221 ;
     RECT  2.34 17.117 30.33 17.339 ;
     RECT  2.34 17.339 25.83 17.411 ;
     RECT  31.392 17.221 40.914 17.411 ;
     RECT  2.34 17.411 19.674 17.609 ;
     RECT  26.748 17.339 30.33 17.923 ;
     RECT  31.392 17.411 40.497 17.923 ;
     RECT  20.484 17.411 25.83 18.193 ;
     RECT  26.748 17.923 40.497 18.193 ;
     RECT  17.856 17.609 19.674 18.265 ;
     RECT  20.484 18.193 40.497 18.265 ;
     RECT  17.856 18.265 40.497 18.301 ;
     RECT  17.856 18.301 40.554 18.761 ;
     RECT  2.34 17.609 17.046 18.769 ;
     RECT  17.856 18.761 40.497 18.769 ;
     RECT  2.34 18.769 40.497 18.869 ;
     RECT  22.572 18.869 40.497 18.959 ;
     RECT  22.824 18.959 40.497 19.535 ;
     RECT  2.34 18.869 21.798 19.651 ;
     RECT  2.34 19.651 22.014 19.849 ;
     RECT  2.34 19.849 22.086 19.877 ;
     RECT  2.376 19.877 22.086 20.011 ;
     RECT  22.824 19.535 27.126 20.011 ;
     RECT  28.008 19.535 28.134 20.389 ;
     RECT  2.376 20.011 27.126 20.417 ;
     RECT  27.9 20.389 28.134 20.425 ;
     RECT  29.052 19.535 40.497 20.425 ;
     RECT  2.415 20.417 27.126 20.461 ;
     RECT  27.9 20.425 40.497 20.461 ;
     RECT  2.415 20.461 40.497 20.579 ;
     RECT  27.432 20.579 40.497 20.893 ;
     RECT  2.415 20.579 26.658 20.921 ;
     RECT  20.988 20.921 26.658 20.957 ;
     RECT  27.432 20.893 40.626 20.993 ;
     RECT  27.72 20.993 40.626 21.155 ;
     RECT  28.512 21.155 40.626 21.199 ;
     RECT  27.72 21.155 27.738 21.389 ;
     RECT  28.512 21.199 40.698 21.389 ;
     RECT  28.512 21.389 40.554 21.533 ;
     RECT  2.415 20.921 20.142 21.811 ;
     RECT  21.42 20.957 26.658 21.811 ;
     RECT  2.304 21.811 20.574 21.901 ;
     RECT  21.42 21.811 26.766 21.901 ;
     RECT  28.512 21.533 40.497 22.081 ;
     RECT  2.304 21.901 27.558 22.171 ;
     RECT  28.296 22.081 40.497 22.171 ;
     RECT  2.304 22.171 40.497 22.235 ;
     RECT  2.415 22.235 26.946 22.253 ;
     RECT  2.415 22.253 19.926 22.981 ;
     RECT  20.7 22.253 26.946 22.981 ;
     RECT  2.415 22.981 26.946 23.161 ;
     RECT  27.684 22.235 40.497 23.161 ;
     RECT  2.415 23.161 40.914 23.323 ;
     RECT  2.304 23.323 40.914 23.585 ;
     RECT  2.304 23.585 28.026 23.741 ;
     RECT  15.912 23.741 28.026 23.819 ;
     RECT  28.764 23.585 40.914 24.233 ;
     RECT  22.536 23.819 28.026 24.359 ;
     RECT  22.536 24.359 26.874 24.395 ;
     RECT  28.764 24.233 40.497 24.395 ;
     RECT  27.612 24.359 28.026 24.475 ;
     RECT  28.764 24.395 33.282 24.475 ;
     RECT  15.912 23.819 21.798 24.571 ;
     RECT  22.536 24.395 26.838 24.571 ;
     RECT  2.304 23.741 15.066 25.051 ;
     RECT  15.912 24.571 26.838 25.051 ;
     RECT  2.304 25.051 26.838 25.24 ;
     RECT  2.304 25.24 26.874 25.277 ;
     RECT  27.612 24.475 33.282 25.285 ;
     RECT  27.612 25.285 33.498 25.321 ;
     RECT  34.236 24.395 40.497 25.321 ;
     RECT  2.304 25.277 26.838 25.853 ;
     RECT  27.612 25.321 40.497 25.861 ;
     RECT  2.304 25.853 16.794 26.249 ;
     RECT  27.612 25.861 40.59 26.393 ;
     RECT  17.568 25.853 26.838 26.555 ;
     RECT  26.676 26.555 26.838 26.599 ;
     RECT  27.612 26.393 40.497 26.599 ;
     RECT  17.568 26.555 25.542 26.789 ;
     RECT  17.568 26.789 21.474 26.813 ;
     RECT  2.34 26.249 16.794 26.869 ;
     RECT  17.568 26.813 21.15 26.869 ;
     RECT  2.34 26.869 21.15 26.969 ;
     RECT  2.34 26.969 21.114 27.599 ;
     RECT  2.34 27.599 20.898 27.635 ;
     RECT  22.284 26.789 25.542 27.869 ;
     RECT  22.32 27.869 25.434 28.013 ;
     RECT  26.676 26.599 40.497 28.021 ;
     RECT  2.34 27.635 20.826 28.381 ;
     RECT  2.34 28.381 20.97 28.687 ;
     RECT  22.644 28.013 25.434 29.291 ;
     RECT  26.532 28.021 40.497 29.497 ;
     RECT  2.34 28.687 21.546 29.561 ;
     RECT  22.68 29.291 25.434 29.669 ;
     RECT  2.34 29.561 16.326 29.759 ;
     RECT  17.1 29.561 21.546 29.795 ;
     RECT  17.28 29.795 21.546 30.209 ;
     RECT  17.352 30.209 21.546 30.221 ;
     RECT  26.46 29.497 40.497 30.271 ;
     RECT  22.752 29.669 25.434 30.415 ;
     RECT  26.244 30.271 40.497 30.415 ;
     RECT  2.415 29.759 16.326 30.451 ;
     RECT  22.752 30.415 40.497 30.641 ;
     RECT  27.72 30.641 40.497 30.685 ;
     RECT  2.415 30.451 16.362 30.721 ;
     RECT  2.415 30.721 16.398 30.955 ;
     RECT  17.352 30.221 21.366 30.955 ;
     RECT  22.752 30.641 26.694 30.991 ;
     RECT  27.72 30.685 40.554 30.991 ;
     RECT  22.716 30.991 26.694 31.019 ;
     RECT  27.72 30.991 40.842 31.253 ;
     RECT  22.716 31.019 26.55 31.261 ;
     RECT  2.415 30.955 21.366 31.339 ;
     RECT  27.72 31.253 40.497 31.379 ;
     RECT  27.72 31.379 38.61 31.459 ;
     RECT  39.348 31.379 40.497 31.523 ;
     RECT  2.415 31.339 21.582 31.531 ;
     RECT  22.644 31.261 26.55 31.649 ;
     RECT  26.244 31.649 26.55 31.801 ;
     RECT  27.576 31.459 38.61 32.071 ;
     RECT  27.504 32.071 38.61 32.107 ;
     RECT  2.415 31.531 21.762 32.155 ;
     RECT  2.415 32.155 21.798 32.225 ;
     RECT  26.244 31.801 26.658 32.341 ;
     RECT  27.396 32.107 38.61 32.341 ;
     RECT  39.42 31.523 40.497 32.341 ;
     RECT  2.415 32.225 21.654 32.495 ;
     RECT  18.576 32.495 21.654 32.567 ;
     RECT  22.644 31.649 25.434 32.701 ;
     RECT  26.244 32.341 40.497 32.701 ;
     RECT  18.615 32.567 21.654 33.449 ;
     RECT  2.415 32.495 17.802 33.511 ;
     RECT  18.615 33.449 21.474 33.539 ;
     RECT  2.376 33.511 17.802 33.581 ;
     RECT  22.644 32.701 40.497 33.691 ;
     RECT  18.615 33.539 21.438 33.889 ;
     RECT  22.284 33.691 40.497 34.429 ;
     RECT  22.284 34.429 40.554 34.763 ;
     RECT  22.356 34.763 40.554 34.889 ;
     RECT  18.54 33.889 21.438 34.997 ;
     RECT  22.356 34.889 40.497 34.997 ;
     RECT  2.415 33.581 17.802 35.131 ;
     RECT  18.576 34.997 21.438 35.311 ;
     RECT  22.392 34.997 40.497 35.707 ;
     RECT  2.34 35.131 17.802 35.851 ;
     RECT  18.576 35.311 21.474 35.851 ;
     RECT  2.34 35.851 21.474 35.885 ;
     RECT  22.392 35.707 40.554 35.969 ;
     RECT  16.2 35.885 21.474 35.981 ;
     RECT  16.2 35.981 21.078 36.005 ;
     RECT  22.392 35.969 25.434 36.049 ;
     RECT  21.888 36.049 25.434 36.149 ;
     RECT  26.388 35.969 40.554 36.239 ;
     RECT  21.888 36.149 25.218 36.275 ;
     RECT  26.388 36.239 40.497 36.751 ;
     RECT  21.924 36.275 25.218 37.021 ;
     RECT  2.34 35.885 15.462 37.129 ;
     RECT  16.272 36.005 21.078 37.129 ;
     RECT  2.34 37.129 21.078 37.319 ;
     RECT  21.924 37.021 25.362 37.327 ;
     RECT  26.28 36.751 40.497 37.327 ;
     RECT  21.924 37.327 40.497 37.499 ;
     RECT  21.924 37.499 25.506 37.561 ;
     RECT  21.672 37.561 25.506 37.589 ;
     RECT  26.388 37.499 40.497 37.769 ;
     RECT  2.34 37.319 20.538 38.129 ;
     RECT  15.408 38.129 20.538 38.209 ;
     RECT  21.672 37.589 25.398 38.209 ;
     RECT  15.408 38.209 25.398 38.371 ;
     RECT  15.408 38.371 25.722 38.399 ;
     RECT  15.588 38.399 25.722 38.551 ;
     RECT  26.46 37.769 40.497 38.551 ;
     RECT  15.588 38.551 40.497 38.669 ;
     RECT  21.456 38.669 25.578 38.705 ;
     RECT  26.46 38.669 40.497 38.749 ;
     RECT  15.588 38.669 20.682 38.765 ;
     RECT  2.34 38.129 14.634 38.777 ;
     RECT  15.588 38.765 20.466 38.939 ;
     RECT  26.46 38.749 40.554 38.947 ;
     RECT  21.456 38.705 25.542 38.975 ;
     RECT  26.46 38.947 40.77 39.209 ;
     RECT  2.376 38.777 14.634 39.217 ;
     RECT  15.588 38.939 20.322 39.217 ;
     RECT  21.456 38.975 25.182 39.245 ;
     RECT  26.46 39.209 40.554 39.245 ;
     RECT  26.46 39.245 40.497 39.487 ;
     RECT  2.376 39.217 20.322 39.749 ;
     RECT  21.672 39.245 25.182 39.749 ;
     RECT  26.1 39.487 40.497 39.785 ;
     RECT  26.784 39.785 40.497 39.821 ;
     RECT  16.704 39.749 20.322 39.901 ;
     RECT  21.672 39.749 24.894 40.135 ;
     RECT  16.704 39.901 20.466 40.171 ;
     RECT  2.376 39.749 15.93 40.433 ;
     RECT  21.384 40.135 24.894 40.507 ;
     RECT  25.668 39.991 25.866 40.507 ;
     RECT  16.704 40.171 20.61 40.559 ;
     RECT  21.384 40.507 25.866 40.559 ;
     RECT  26.82 39.821 40.497 40.639 ;
     RECT  2.415 40.433 15.93 40.675 ;
     RECT  16.704 40.559 20.574 40.675 ;
     RECT  26.82 40.639 40.554 40.711 ;
     RECT  21.42 40.559 25.866 40.739 ;
     RECT  26.748 40.711 40.554 40.837 ;
     RECT  26.748 40.837 40.662 40.909 ;
     RECT  26.748 40.909 40.806 40.945 ;
     RECT  23.796 40.739 25.866 40.981 ;
     RECT  26.748 40.945 40.842 40.981 ;
     RECT  2.415 40.675 20.574 41.251 ;
     RECT  2.376 41.251 20.574 41.341 ;
     RECT  21.42 40.739 22.95 41.369 ;
     RECT  23.796 40.981 40.842 41.369 ;
     RECT  31.104 41.369 40.806 41.441 ;
     RECT  23.796 41.369 30.366 41.477 ;
     RECT  21.816 41.369 22.95 41.485 ;
     RECT  23.796 41.477 26.478 41.485 ;
     RECT  2.376 41.341 20.61 41.521 ;
     RECT  27.216 41.477 30.366 41.549 ;
     RECT  2.376 41.521 21.042 41.675 ;
     RECT  27.288 41.549 30.366 41.675 ;
     RECT  21.816 41.485 26.478 41.909 ;
     RECT  2.376 41.675 13.59 42.089 ;
     RECT  27.36 41.675 30.366 42.151 ;
     RECT  31.104 41.441 40.662 42.151 ;
     RECT  2.415 42.089 13.59 42.179 ;
     RECT  14.436 41.675 21.042 42.187 ;
     RECT  21.816 41.909 26.226 42.187 ;
     RECT  14.436 42.187 26.226 42.359 ;
     RECT  27.36 42.151 40.662 42.449 ;
     RECT  27.36 42.449 40.554 42.457 ;
     RECT  27.288 42.457 40.554 42.557 ;
     RECT  10.584 42.179 13.59 42.601 ;
     RECT  14.436 42.359 21.114 42.601 ;
     RECT  21.888 42.359 26.226 42.749 ;
     RECT  21.888 42.749 25.434 42.755 ;
     RECT  26.172 42.749 26.226 43.069 ;
     RECT  27.288 42.557 40.497 43.069 ;
     RECT  10.584 42.601 21.114 43.105 ;
     RECT  2.415 42.179 9.846 43.141 ;
     RECT  10.584 43.105 21.222 43.141 ;
     RECT  2.415 43.141 21.222 43.267 ;
     RECT  21.996 42.755 25.434 43.295 ;
     RECT  2.412 43.267 21.222 43.325 ;
     RECT  2.415 43.325 21.222 43.331 ;
     RECT  2.415 43.331 16.506 43.367 ;
     RECT  17.352 43.331 21.222 43.681 ;
     RECT  26.172 43.069 40.497 43.835 ;
     RECT  17.352 43.681 21.366 44.105 ;
     RECT  17.352 44.105 19.062 44.113 ;
     RECT  20.088 44.105 21.366 44.185 ;
     RECT  22.14 43.295 25.434 44.185 ;
     RECT  2.415 43.367 16.434 44.539 ;
     RECT  2.376 44.539 16.434 44.581 ;
     RECT  17.244 44.113 19.062 44.653 ;
     RECT  2.34 44.581 16.434 44.725 ;
     RECT  17.208 44.653 19.062 44.725 ;
     RECT  20.088 44.185 25.578 44.725 ;
     RECT  26.352 43.835 40.497 44.725 ;
     RECT  20.088 44.725 40.497 45.031 ;
     RECT  19.98 45.031 40.497 45.185 ;
     RECT  2.34 44.725 19.062 45.257 ;
     RECT  2.34 45.257 16.542 45.419 ;
     RECT  2.415 45.419 16.542 45.455 ;
     RECT  18.615 45.257 19.062 45.535 ;
     RECT  21.348 45.185 40.497 45.725 ;
     RECT  20.052 45.185 20.61 45.931 ;
     RECT  21.348 45.725 21.762 45.931 ;
     RECT  18.615 45.535 19.17 46.111 ;
     RECT  22.644 45.725 40.497 46.111 ;
     RECT  18.252 46.111 19.206 46.123 ;
     RECT  20.052 45.931 21.762 46.123 ;
     RECT  22.644 46.111 40.914 46.229 ;
     RECT  22.68 46.229 40.914 46.337 ;
     RECT  2.415 45.455 16.506 46.345 ;
     RECT  17.244 46.111 17.262 46.345 ;
     RECT  2.415 46.345 17.334 46.381 ;
     RECT  18.252 46.123 21.762 46.381 ;
     RECT  2.415 46.381 21.762 46.651 ;
     RECT  2.415 46.651 21.87 47.191 ;
     RECT  22.68 46.337 40.497 47.191 ;
     RECT  2.415 47.191 40.497 47.309 ;
     RECT  2.415 47.309 22.41 47.731 ;
     RECT  2.376 47.731 22.41 47.849 ;
     RECT  2.415 47.849 22.41 47.885 ;
     RECT  19.728 47.885 22.41 48.127 ;
     RECT  23.364 47.309 40.497 48.127 ;
     RECT  19.728 48.127 40.497 48.263 ;
     RECT  19.764 48.263 40.497 48.425 ;
     RECT  37.728 48.425 40.497 48.461 ;
     RECT  2.415 47.885 18.99 48.661 ;
     RECT  2.34 48.661 18.99 48.965 ;
     RECT  2.415 48.965 18.99 49.003 ;
     RECT  19.764 48.425 36.99 49.003 ;
     RECT  37.728 48.461 38.034 49.351 ;
     RECT  38.808 48.461 40.497 49.351 ;
     RECT  2.415 49.003 36.99 49.469 ;
     RECT  19.908 49.469 36.99 49.477 ;
     RECT  37.728 49.351 40.497 49.477 ;
     RECT  19.908 49.477 40.497 50.045 ;
     RECT  2.415 49.469 19.062 50.051 ;
     RECT  19.908 50.045 26.766 50.141 ;
     RECT  22.716 50.141 26.766 50.315 ;
     RECT  19.908 50.141 21.69 50.351 ;
     RECT  27.684 50.045 40.497 50.701 ;
     RECT  22.86 50.315 26.766 50.827 ;
     RECT  22.86 50.827 26.91 50.935 ;
     RECT  27.684 50.701 40.554 50.935 ;
     RECT  2.415 50.051 19.026 50.971 ;
     RECT  19.908 50.351 21.654 50.971 ;
     RECT  22.86 50.935 40.554 50.971 ;
     RECT  22.86 50.971 40.662 51.197 ;
     RECT  22.86 51.197 40.554 51.245 ;
     RECT  2.415 50.971 21.654 51.367 ;
     RECT  23.58 51.245 40.554 51.467 ;
     RECT  2.415 51.367 21.942 51.511 ;
     RECT  2.376 51.511 21.942 51.943 ;
     RECT  2.376 51.943 22.05 52.249 ;
     RECT  23.58 51.467 40.497 52.321 ;
     RECT  23.22 52.321 40.497 52.483 ;
     RECT  23.22 52.483 40.59 52.555 ;
     RECT  2.376 52.249 22.446 52.583 ;
     RECT  18.615 52.583 22.446 52.591 ;
     RECT  23.22 52.555 40.626 52.591 ;
     RECT  2.376 52.583 17.874 52.619 ;
     RECT  18.615 52.591 40.626 52.681 ;
     RECT  18.615 52.681 40.77 52.889 ;
     RECT  2.376 52.619 17.586 53.015 ;
     RECT  32.148 52.889 40.77 53.249 ;
     RECT  2.415 53.015 17.586 53.365 ;
     RECT  2.415 53.365 17.658 53.563 ;
     RECT  18.615 52.889 31.374 53.825 ;
     RECT  18.615 53.825 27.126 53.837 ;
     RECT  32.148 53.249 40.626 54.043 ;
     RECT  2.415 53.563 17.694 54.067 ;
     RECT  18.615 53.837 22.842 54.067 ;
     RECT  2.415 54.067 22.842 54.095 ;
     RECT  27.864 53.825 31.374 54.211 ;
     RECT  32.112 54.043 40.626 54.211 ;
     RECT  27.864 54.211 40.626 54.329 ;
     RECT  32.112 54.329 40.554 54.365 ;
     RECT  27.864 54.329 31.23 54.401 ;
     RECT  23.58 53.837 27.126 54.473 ;
     RECT  23.724 54.473 27.126 54.571 ;
     RECT  27.864 54.401 31.086 54.571 ;
     RECT  2.415 54.095 22.158 54.751 ;
     RECT  2.376 54.751 22.158 55.021 ;
     RECT  22.932 54.949 22.95 55.021 ;
     RECT  23.724 54.571 31.086 55.291 ;
     RECT  32.112 54.365 40.497 55.291 ;
     RECT  2.376 55.021 22.95 55.489 ;
     RECT  23.724 55.291 40.497 55.489 ;
     RECT  2.376 55.489 40.626 55.525 ;
     RECT  2.376 55.525 40.662 55.687 ;
     RECT  2.376 55.687 40.77 55.715 ;
     RECT  2.376 55.715 17.658 55.751 ;
     RECT  18.504 55.715 40.77 55.787 ;
     RECT  31.932 55.787 40.77 55.853 ;
     RECT  34.56 55.853 40.77 56.219 ;
     RECT  2.415 55.751 17.658 56.533 ;
     RECT  18.504 55.787 31.158 56.533 ;
     RECT  31.932 55.853 33.714 56.641 ;
     RECT  34.56 56.219 40.662 56.641 ;
     RECT  2.415 56.533 31.158 56.759 ;
     RECT  23.904 56.759 31.158 56.875 ;
     RECT  23.904 56.875 31.194 57.019 ;
     RECT  31.932 56.641 40.662 57.019 ;
     RECT  2.415 56.759 23.13 57.073 ;
     RECT  23.904 57.019 40.662 57.145 ;
     RECT  23.904 57.145 40.77 57.209 ;
     RECT  28.26 57.209 40.77 57.299 ;
     RECT  28.944 57.299 40.662 57.371 ;
     RECT  29.016 57.371 40.662 57.443 ;
     RECT  29.088 57.443 40.662 57.479 ;
     RECT  23.904 57.209 27.342 57.533 ;
     RECT  23.904 57.533 25.578 57.569 ;
     RECT  26.496 57.533 27.342 57.569 ;
     RECT  29.415 57.479 40.662 57.569 ;
     RECT  2.376 57.073 23.13 57.577 ;
     RECT  23.904 57.569 24.57 57.577 ;
     RECT  33.264 57.569 40.662 57.581 ;
     RECT  2.376 57.577 24.57 57.605 ;
     RECT  29.415 57.569 30.114 57.641 ;
     RECT  31.608 57.569 31.626 57.641 ;
     RECT  2.376 57.605 21.258 57.677 ;
     RECT  29.415 57.641 30.006 57.677 ;
     RECT  33.264 57.581 38.97 57.677 ;
     RECT  33.264 57.677 33.282 57.713 ;
     RECT  34.02 57.677 38.97 57.725 ;
     RECT  22.104 57.605 24.57 57.749 ;
     RECT  29.415 57.677 29.754 57.749 ;
     RECT  34.02 57.725 34.038 57.749 ;
     RECT  2.376 57.677 19.89 57.839 ;
     RECT  21.024 57.677 21.258 57.839 ;
     RECT  24.015 57.749 24.57 57.839 ;
     RECT  34.815 57.725 38.97 57.839 ;
     RECT  39.924 57.581 40.662 57.839 ;
     RECT  34.815 57.839 36.738 57.869 ;
     RECT  22.104 57.749 22.878 57.875 ;
     RECT  37.656 57.839 37.674 57.875 ;
     RECT  39.924 57.839 40.497 57.875 ;
     RECT  7.704 57.839 19.89 57.911 ;
     RECT  21.24 57.839 21.258 57.911 ;
     RECT  22.104 57.875 22.842 57.911 ;
     RECT  2.376 57.839 6.714 57.983 ;
     RECT  7.815 57.911 19.89 57.983 ;
     RECT  22.824 57.911 22.842 57.983 ;
     RECT  26.604 57.569 26.622 57.983 ;
     RECT  7.815 57.983 16.974 58.019 ;
     RECT  18 57.983 19.89 58.019 ;
     RECT  38.412 57.839 38.97 58.019 ;
     RECT  24.015 57.839 24.297 58.067 ;
     RECT  29.415 57.749 29.697 58.067 ;
     RECT  34.815 57.869 35.946 58.067 ;
     RECT  40.215 57.875 40.497 58.067 ;
     RECT  2.412 57.983 6.714 58.109 ;
     RECT  7.815 58.019 16.542 58.109 ;
     RECT  18 58.019 19.17 58.109 ;
     RECT  35.784 58.067 35.946 58.109 ;
     RECT  36.72 57.869 36.738 58.109 ;
     RECT  38.412 58.019 38.574 58.109 ;
     RECT  5.04 58.109 6.642 58.145 ;
     RECT  7.815 58.109 14.094 58.145 ;
     RECT  15.264 58.109 16.038 58.145 ;
     RECT  18 58.109 19.098 58.145 ;
     RECT  35.784 58.109 35.802 58.145 ;
     RECT  38.412 58.109 38.43 58.145 ;
     RECT  2.412 58.109 2.862 58.157 ;
     RECT  3.924 58.109 3.942 58.157 ;
     RECT  7.815 58.145 13.374 58.181 ;
     RECT  15.264 58.145 15.822 58.181 ;
     RECT  7.815 58.181 13.305 58.217 ;
     RECT  6.624 58.145 6.642 58.253 ;
     RECT  2.415 58.157 2.505 58.337 ;
     RECT  7.815 58.217 7.905 58.337 ;
     RECT  8.856 58.217 13.305 58.337 ;
     RECT  18.615 58.145 18.705 58.337 ;
     RECT  24.015 58.067 24.105 58.337 ;
     RECT  29.415 58.067 29.505 58.337 ;
     RECT  34.815 58.067 34.905 58.337 ;
     RECT  40.215 58.067 40.305 58.337 ;
     RECT  8.856 58.337 12.87 58.721 ;
     RECT  8.856 58.721 11.358 58.829 ;
     RECT  8.856 58.829 11.322 59.309 ;
     RECT  9 59.309 11.322 59.845 ;
     RECT  12.312 58.721 12.69 59.873 ;
     RECT  12.456 59.873 12.69 59.885 ;
     RECT  12.456 59.885 12.474 59.954 ;
     RECT  9 59.845 11.466 60.348 ;
    LAYER M4 ;
     RECT  0.156 14.88 0.275 15.192 ;
     RECT  2.293 2.88 2.408 3.96 ;
     RECT  2.293 5.184 2.408 5.208 ;
     RECT  2.293 7.92 2.408 7.944 ;
     RECT  2.293 9.072 2.408 9.336 ;
     RECT  2.285 10.32 2.408 10.344 ;
     RECT  2.401 13.296 2.408 13.32 ;
     RECT  0.275 15.024 2.408 15.192 ;
     RECT  2.365 17.616 2.408 17.64 ;
     RECT  2.252 22.176 2.408 22.2 ;
     RECT  2.285 23.376 2.408 23.4 ;
     RECT  0.229 30.384 2.408 30.408 ;
     RECT  2.365 33.552 2.408 33.576 ;
     RECT  2.365 35.712 2.408 35.736 ;
     RECT  2.365 38.16 2.408 38.184 ;
     RECT  2.293 43.296 2.408 43.32 ;
     RECT  2.293 44.544 2.408 44.568 ;
     RECT  2.329 48.672 2.408 48.696 ;
     RECT  2.401 58.128 2.408 58.152 ;
     RECT  2.408 2.148 2.512 58.332 ;
     RECT  2.512 2.418 2.704 58.152 ;
     RECT  2.704 17.616 2.819 20.184 ;
     RECT  2.704 7.824 2.867 9.336 ;
     RECT  2.867 7.92 2.963 9.336 ;
     RECT  2.704 2.784 2.981 5.544 ;
     RECT  2.704 11.808 2.981 12.216 ;
     RECT  2.704 25.248 2.981 26.28 ;
     RECT  2.981 2.784 3.161 5.496 ;
     RECT  2.819 18.384 3.197 20.184 ;
     RECT  2.704 33.552 3.251 35.928 ;
     RECT  2.704 47.568 3.341 49.176 ;
     RECT  3.341 48.96 3.377 49.176 ;
     RECT  2.704 53.52 3.413 53.976 ;
     RECT  2.704 21.6 3.443 21.624 ;
     RECT  2.704 40.56 3.485 41.64 ;
     RECT  2.704 43.536 3.485 43.56 ;
     RECT  3.251 33.552 3.521 34.152 ;
     RECT  3.485 40.56 3.557 41.064 ;
     RECT  2.704 45.6 3.557 45.624 ;
     RECT  2.704 28.944 3.629 30.408 ;
     RECT  3.161 4.128 3.635 5.496 ;
     RECT  2.704 38.16 3.692 38.712 ;
     RECT  3.197 18.672 3.701 20.184 ;
     RECT  3.701 18.672 3.724 19.464 ;
     RECT  3.692 38.16 3.733 38.952 ;
     RECT  2.981 11.808 3.773 12.024 ;
     RECT  2.704 52.368 3.877 52.44 ;
     RECT  3.377 48.96 3.881 49.032 ;
     RECT  3.341 47.568 3.917 47.592 ;
     RECT  3.877 52.368 3.917 52.488 ;
     RECT  2.704 58.128 3.953 58.152 ;
     RECT  2.704 6.672 4.021 6.696 ;
     RECT  2.963 8.16 4.021 9.336 ;
     RECT  3.949 10.8 4.021 10.824 ;
     RECT  3.773 12 4.061 12.024 ;
     RECT  4.021 6.672 4.067 10.824 ;
     RECT  4.067 9.504 4.133 10.824 ;
     RECT  2.981 25.248 4.169 25.464 ;
     RECT  3.413 53.952 4.213 53.976 ;
     RECT  3.841 55.872 4.259 55.896 ;
     RECT  3.629 28.944 4.268 28.968 ;
     RECT  3.521 33.792 4.268 34.152 ;
     RECT  2.704 13.296 4.309 14.136 ;
     RECT  4.268 33.792 4.309 34.536 ;
     RECT  3.251 35.904 4.309 35.928 ;
     RECT  4.067 6.672 4.313 8.424 ;
     RECT  4.213 53.952 4.313 54.6 ;
     RECT  4.313 54.336 4.345 54.6 ;
     RECT  4.268 28.416 4.355 28.968 ;
     RECT  4.309 33.792 4.355 35.928 ;
     RECT  4.268 37.008 4.355 37.032 ;
     RECT  3.917 52.464 4.412 52.488 ;
     RECT  4.309 13.296 4.421 14.904 ;
     RECT  4.165 20.592 4.453 20.616 ;
     RECT  2.704 27.312 4.453 27.336 ;
     RECT  4.412 22.416 4.499 22.44 ;
     RECT  4.355 33.792 4.529 34.152 ;
     RECT  4.453 27.072 4.565 27.336 ;
     RECT  3.733 38.016 4.597 38.952 ;
     RECT  4.345 54.336 4.601 55.32 ;
     RECT  3.635 4.944 4.633 5.112 ;
     RECT  3.629 30.384 4.633 30.408 ;
     RECT  4.355 35.136 4.633 35.928 ;
     RECT  4.597 37.2 4.681 38.952 ;
     RECT  4.549 42.768 4.741 42.792 ;
     RECT  4.412 52.464 4.789 52.92 ;
     RECT  3.161 2.784 4.813 2.952 ;
     RECT  4.681 38.016 4.817 38.952 ;
     RECT  4.601 54.336 4.817 54.744 ;
     RECT  4.817 54.336 4.835 54.6 ;
     RECT  4.309 46.752 4.849 46.776 ;
     RECT  4.169 25.248 4.885 25.272 ;
     RECT  4.813 2.784 4.921 3.144 ;
     RECT  4.633 4.512 4.921 5.112 ;
     RECT  3.724 18.672 4.931 18.696 ;
     RECT  4.849 46.656 4.993 46.776 ;
     RECT  4.421 13.584 5.027 14.904 ;
     RECT  2.704 15.984 5.027 16.008 ;
     RECT  4.133 10.8 5.029 10.824 ;
     RECT  3.697 40.128 5.033 40.488 ;
     RECT  4.741 42.768 5.033 43.464 ;
     RECT  4.813 44.448 5.036 44.472 ;
     RECT  4.993 46.176 5.036 46.776 ;
     RECT  4.529 33.792 5.077 33.816 ;
     RECT  5.036 44.448 5.077 46.776 ;
     RECT  4.633 35.136 5.123 35.976 ;
     RECT  5.077 44.448 5.123 47.592 ;
     RECT  5.077 33.6 5.132 33.816 ;
     RECT  4.313 6.816 5.137 8.424 ;
     RECT  4.133 9.504 5.137 9.528 ;
     RECT  4.789 52.464 5.141 53.016 ;
     RECT  3.841 56.976 5.141 57 ;
     RECT  5.137 6.816 5.213 9.528 ;
     RECT  5.123 46.176 5.213 46.2 ;
     RECT  4.565 27.072 5.281 27.096 ;
     RECT  5.213 9.312 5.285 9.528 ;
     RECT  5.132 32.688 5.285 33.816 ;
     RECT  4.453 20.592 5.357 21.144 ;
     RECT  4.921 2.784 5.365 5.112 ;
     RECT  4.885 24.624 5.372 25.272 ;
     RECT  5.372 24.048 5.459 25.272 ;
     RECT  5.459 25.248 5.465 25.272 ;
     RECT  5.033 40.272 5.465 40.488 ;
     RECT  5.365 2.784 5.537 5.208 ;
     RECT  5.123 44.448 5.581 45.048 ;
     RECT  5.029 10.8 5.603 11.592 ;
     RECT  3.985 17.664 5.609 17.688 ;
     RECT  5.389 12.72 5.617 13.128 ;
     RECT  4.993 19.008 5.677 19.032 ;
     RECT  5.537 2.784 5.699 3.96 ;
     RECT  4.817 38.016 5.717 38.04 ;
     RECT  5.033 43.44 5.753 43.464 ;
     RECT  5.413 22.752 5.825 22.776 ;
     RECT  5.537 4.944 5.845 5.208 ;
     RECT  5.213 6.816 5.845 8.184 ;
     RECT  5.845 4.944 5.897 8.184 ;
     RECT  5.285 9.504 5.897 9.528 ;
     RECT  5.897 4.944 5.932 5.928 ;
     RECT  5.285 32.688 5.933 33.624 ;
     RECT  5.677 19.008 6.001 19.32 ;
     RECT  6.001 18.96 6.005 19.32 ;
     RECT  5.641 55.872 6.005 55.896 ;
     RECT  4.355 28.944 6.037 28.968 ;
     RECT  5.699 2.784 6.041 3.432 ;
     RECT  3.985 31.536 6.145 31.56 ;
     RECT  5.933 32.688 6.145 33.288 ;
     RECT  5.123 35.136 6.145 35.736 ;
     RECT  6.073 42.144 6.217 42.168 ;
     RECT  6.037 28.416 6.221 29.112 ;
     RECT  6.217 42.144 6.253 42.408 ;
     RECT  5.123 47.568 6.277 47.592 ;
     RECT  3.881 49.008 6.277 49.032 ;
     RECT  5.281 26.448 6.293 27.096 ;
     RECT  5.027 14.16 6.325 14.808 ;
     RECT  6.277 47.568 6.329 49.032 ;
     RECT  5.581 44.448 6.357 44.472 ;
     RECT  6.329 48.288 6.364 49.032 ;
     RECT  4.885 50.736 6.401 50.76 ;
     RECT  6.145 31.536 6.473 33.288 ;
     RECT  4.633 30.384 6.505 30.504 ;
     RECT  6.473 31.536 6.505 32.52 ;
     RECT  6.541 23.808 6.649 24.504 ;
     RECT  6.001 11.664 6.685 11.688 ;
     RECT  6.325 14.16 6.685 15.768 ;
     RECT  6.005 18.96 6.685 19.224 ;
     RECT  5.932 4.944 6.721 5.208 ;
     RECT  5.617 12.72 6.721 12.744 ;
     RECT  6.364 48.672 6.721 49.032 ;
     RECT  6.253 41.856 6.725 42.408 ;
     RECT  4.835 54.576 6.761 54.6 ;
     RECT  6.685 18.864 6.793 19.224 ;
     RECT  5.465 40.464 6.829 40.488 ;
     RECT  6.041 2.784 6.853 3.096 ;
     RECT  6.721 12.72 6.853 12.888 ;
     RECT  6.685 14.016 6.853 15.768 ;
     RECT  6.145 34.608 6.86 35.736 ;
     RECT  6.293 27.072 6.901 27.096 ;
     RECT  6.853 12.72 6.937 15.768 ;
     RECT  6.685 11.664 7.141 11.736 ;
     RECT  6.853 2.256 7.148 3.096 ;
     RECT  6.721 4.704 7.153 5.208 ;
     RECT  5.897 7.056 7.189 8.184 ;
     RECT  7.141 10.752 7.261 11.736 ;
     RECT  6.937 12.72 7.261 16.008 ;
     RECT  6.181 45.552 7.261 45.576 ;
     RECT  7.153 4.512 7.333 5.208 ;
     RECT  7.117 26.064 7.369 26.088 ;
     RECT  6.901 27.072 7.369 27.912 ;
     RECT  7.261 45.264 7.381 45.576 ;
     RECT  7.009 47.28 7.381 47.304 ;
     RECT  6.973 55.248 7.381 55.272 ;
     RECT  7.045 56.352 7.381 56.376 ;
     RECT  6.685 57.6 7.381 57.624 ;
     RECT  5.357 20.592 7.397 21 ;
     RECT  6.86 34.608 7.477 36.216 ;
     RECT  6.613 17.088 7.513 17.112 ;
     RECT  6.793 18.24 7.513 19.224 ;
     RECT  7.261 42.432 7.513 42.456 ;
     RECT  7.397 20.592 7.549 21.24 ;
     RECT  7.477 33.648 7.549 36.216 ;
     RECT  7.381 45.264 7.58 47.304 ;
     RECT  7.333 4.512 7.585 6.072 ;
     RECT  7.189 7.056 7.585 8.952 ;
     RECT  7.369 26.064 7.585 27.912 ;
     RECT  6.221 29.088 7.585 29.112 ;
     RECT  7.477 50.736 7.585 50.76 ;
     RECT  6.829 51.744 7.585 51.768 ;
     RECT  7.585 50.736 7.621 51.768 ;
     RECT  7.513 17.088 7.649 19.224 ;
     RECT  7.549 20.592 7.649 21.432 ;
     RECT  6.757 52.992 7.657 53.016 ;
     RECT  6.901 54.192 7.657 54.216 ;
     RECT  7.649 17.088 7.669 21.672 ;
     RECT  6.649 23.808 7.669 24.792 ;
     RECT  7.549 33.648 7.669 37.032 ;
     RECT  6.793 39.072 7.669 39.096 ;
     RECT  7.148 2.256 7.808 3.336 ;
     RECT  7.585 4.512 7.808 8.952 ;
     RECT  7.261 10.752 7.808 16.008 ;
     RECT  7.669 17.088 7.808 22.056 ;
     RECT  7.669 23.136 7.808 24.792 ;
     RECT  7.585 26.064 7.808 29.112 ;
     RECT  6.505 30.384 7.808 32.52 ;
     RECT  7.669 33.648 7.808 39.096 ;
     RECT  6.829 40.464 7.808 40.68 ;
     RECT  7.513 42.432 7.808 42.744 ;
     RECT  7.58 44.352 7.808 47.304 ;
     RECT  6.721 48.672 7.808 49.56 ;
     RECT  7.621 50.64 7.808 51.768 ;
     RECT  7.657 52.992 7.808 54.216 ;
     RECT  7.381 55.248 7.808 57.624 ;
     RECT  7.808 2.148 7.912 58.332 ;
     RECT  7.912 2.148 8.104 58.062 ;
     RECT  8.104 15.552 8.129 16.056 ;
     RECT  8.104 18.816 8.129 18.84 ;
     RECT  8.104 32.208 8.165 36.504 ;
     RECT  8.104 37.968 8.201 38.184 ;
     RECT  8.104 20.16 8.237 22.824 ;
     RECT  8.104 28.8 8.291 30.504 ;
     RECT  8.237 20.16 8.309 22.056 ;
     RECT  8.104 3.072 8.345 3.48 ;
     RECT  8.165 32.208 8.381 32.424 ;
     RECT  8.104 48.432 8.524 55.368 ;
     RECT  8.104 4.656 8.561 11.736 ;
     RECT  8.104 25.68 8.579 27.096 ;
     RECT  8.104 44.448 8.597 44.472 ;
     RECT  8.104 45.552 8.669 46.872 ;
     RECT  8.561 4.656 8.771 11.688 ;
     RECT  8.579 25.68 8.771 26.76 ;
     RECT  8.104 17.376 8.885 17.736 ;
     RECT  8.669 46.848 8.957 46.872 ;
     RECT  8.104 56.448 8.957 58.008 ;
     RECT  8.593 1.728 9.025 1.752 ;
     RECT  8.165 33.6 9.029 36.504 ;
     RECT  9.029 33.6 9.052 34.152 ;
     RECT  8.845 59.28 9.059 59.304 ;
     RECT  8.104 42.72 9.065 42.744 ;
     RECT  9.025 1.104 9.097 1.752 ;
     RECT  8.771 4.656 9.107 9.72 ;
     RECT  8.104 13.056 9.109 14.28 ;
     RECT  8.129 15.744 9.109 16.056 ;
     RECT  8.104 23.808 9.137 24.6 ;
     RECT  8.201 38.16 9.205 38.184 ;
     RECT  8.104 40.56 9.205 40.584 ;
     RECT  8.104 41.568 9.205 41.592 ;
     RECT  8.345 3.408 9.241 3.48 ;
     RECT  9.107 4.656 9.241 9.432 ;
     RECT  9.205 38.16 9.245 38.424 ;
     RECT  8.957 56.448 9.277 57.624 ;
     RECT  9.205 22.752 9.289 22.776 ;
     RECT  8.524 48.672 9.385 55.368 ;
     RECT  9.277 56.352 9.385 57.624 ;
     RECT  9.109 13.056 9.445 16.056 ;
     RECT  9.089 59.856 9.445 59.88 ;
     RECT  9.097 0.576 9.491 1.752 ;
     RECT  9.445 12.864 9.493 16.056 ;
     RECT  8.291 28.8 9.497 28.824 ;
     RECT  9.245 38.4 9.5 38.424 ;
     RECT  9.205 39.888 9.5 41.592 ;
     RECT  9.445 59.856 9.521 59.976 ;
     RECT  9.493 12.864 9.532 16.68 ;
     RECT  9.5 38.4 9.587 41.592 ;
     RECT  9.521 59.856 9.605 60.024 ;
     RECT  9.532 13.824 9.635 16.68 ;
     RECT  9.241 3.408 9.673 9.432 ;
     RECT  9.587 39.888 9.677 41.592 ;
     RECT  8.291 30.384 9.685 30.504 ;
     RECT  9.493 0.192 9.779 0.552 ;
     RECT  9.029 35.136 9.785 36.504 ;
     RECT  9.685 30.384 9.817 31.224 ;
     RECT  9.635 13.824 9.821 14.232 ;
     RECT  9.779 0.192 9.923 0.312 ;
     RECT  8.669 45.552 9.925 45.576 ;
     RECT  9.385 48.672 9.997 57.624 ;
     RECT  9.677 39.888 10.001 41.256 ;
     RECT  9.491 1.728 10.033 1.752 ;
     RECT  9.673 2.88 10.033 9.432 ;
     RECT  9.817 29.664 10.033 31.224 ;
     RECT  9.673 58.704 10.067 58.776 ;
     RECT  8.309 20.16 10.069 21.672 ;
     RECT  9.313 47.232 10.105 47.256 ;
     RECT  9.997 48.672 10.105 57.672 ;
     RECT  9.605 59.856 10.141 59.928 ;
     RECT  10.105 47.232 10.165 57.672 ;
     RECT  10.033 1.728 10.213 9.432 ;
     RECT  9.635 15.312 10.213 16.68 ;
     RECT  9.397 17.856 10.213 17.88 ;
     RECT  8.771 25.968 10.213 26.76 ;
     RECT  10.033 29.664 10.213 31.368 ;
     RECT  8.381 32.4 10.213 32.424 ;
     RECT  10.213 1.728 10.249 9.864 ;
     RECT  8.771 10.992 10.249 11.688 ;
     RECT  10.069 20.016 10.249 21.672 ;
     RECT  10.213 29.664 10.259 32.424 ;
     RECT  10.259 30.384 10.309 32.424 ;
     RECT  10.213 15.312 10.321 17.88 ;
     RECT  10.309 30.384 10.321 32.52 ;
     RECT  9.052 33.6 10.321 33.816 ;
     RECT  9.923 0.24 10.355 0.312 ;
     RECT  10.141 59.28 10.355 59.928 ;
     RECT  9.785 35.136 10.361 35.544 ;
     RECT  10.001 39.888 10.361 40.584 ;
     RECT  9.961 43.92 10.361 43.944 ;
     RECT  10.213 25.968 10.397 27.24 ;
     RECT  10.213 24.816 10.405 24.84 ;
     RECT  10.397 25.968 10.405 26.808 ;
     RECT  10.321 15.312 10.453 18.216 ;
     RECT  10.405 24.816 10.499 26.808 ;
     RECT  10.117 28.272 10.508 28.296 ;
     RECT  10.499 24.816 10.541 26.28 ;
     RECT  10.508 28.272 10.597 28.68 ;
     RECT  10.249 1.728 10.604 11.688 ;
     RECT  10.537 13.104 10.604 13.128 ;
     RECT  9.137 23.808 10.609 23.832 ;
     RECT  9.925 45.552 10.609 46.152 ;
     RECT  10.165 47.232 10.609 58.152 ;
     RECT  10.453 15.312 10.643 18.888 ;
     RECT  10.355 59.856 10.643 59.928 ;
     RECT  9.587 38.4 10.717 38.424 ;
     RECT  9.821 14.208 10.748 14.232 ;
     RECT  10.643 15.312 10.748 16.92 ;
     RECT  10.609 23.808 10.748 24.408 ;
     RECT  10.249 20.016 10.753 21.816 ;
     RECT  10.609 45.552 10.757 58.152 ;
     RECT  10.757 47.856 10.78 58.152 ;
     RECT  10.321 30.384 10.793 33.816 ;
     RECT  10.717 37.584 10.801 38.424 ;
     RECT  10.748 23.328 10.835 24.408 ;
     RECT  10.753 19.968 10.861 21.816 ;
     RECT  10.604 1.728 10.865 13.128 ;
     RECT  10.801 37.92 10.973 38.424 ;
     RECT  10.361 40.464 11.009 40.584 ;
     RECT  11.009 40.56 11.041 40.584 ;
     RECT  10.835 23.808 11.081 24.408 ;
     RECT  11.041 40.56 11.081 40.776 ;
     RECT  10.865 10.272 11.132 13.128 ;
     RECT  10.748 14.208 11.132 16.92 ;
     RECT  10.643 18.528 11.149 18.888 ;
     RECT  10.861 19.968 11.149 22.008 ;
     RECT  11.149 18.528 11.153 22.008 ;
     RECT  10.78 48.96 11.173 58.152 ;
     RECT  11.077 0.48 11.249 0.504 ;
     RECT  10.793 31.584 11.324 33.816 ;
     RECT  10.597 28.176 11.329 28.68 ;
     RECT  11.149 43.152 11.365 43.176 ;
     RECT  11.185 44.448 11.365 44.472 ;
     RECT  11.173 48.96 11.369 58.68 ;
     RECT  11.365 43.152 11.372 44.472 ;
     RECT  11.369 48.96 11.405 57.624 ;
     RECT  11.369 58.656 11.405 58.68 ;
     RECT  11.372 42.72 11.413 44.472 ;
     RECT  11.153 18.528 11.441 21.816 ;
     RECT  11.324 31.584 11.441 33.912 ;
     RECT  11.132 10.272 11.549 16.92 ;
     RECT  11.441 18.528 11.549 20.952 ;
     RECT  11.329 28.176 11.557 28.776 ;
     RECT  10.361 35.136 11.581 35.16 ;
     RECT  11.081 24.096 11.621 24.408 ;
     RECT  11.557 27.36 11.657 28.776 ;
     RECT  11.081 40.752 11.747 40.776 ;
     RECT  11.441 31.728 11.765 33.912 ;
     RECT  11.765 33.024 11.797 33.912 ;
     RECT  11.581 34.896 11.797 35.16 ;
     RECT  11.365 39.312 11.833 39.336 ;
     RECT  10.757 45.552 11.843 46.824 ;
     RECT  10.865 1.728 11.845 9.288 ;
     RECT  11.549 10.272 11.845 16.392 ;
     RECT  11.621 24.144 11.873 24.408 ;
     RECT  10.541 25.584 11.941 26.28 ;
     RECT  11.413 41.76 11.941 44.472 ;
     RECT  11.941 41.76 12.025 45 ;
     RECT  11.797 33.024 12.125 35.16 ;
     RECT  11.249 0.48 12.157 0.552 ;
     RECT  12.125 33.984 12.157 35.16 ;
     RECT  11.657 27.888 12.161 28.776 ;
     RECT  11.843 46.08 12.161 46.104 ;
     RECT  12.157 0.336 12.181 0.552 ;
     RECT  11.941 25.296 12.193 26.28 ;
     RECT  11.977 22.848 12.265 22.872 ;
     RECT  11.833 39.312 12.277 39.48 ;
     RECT  10.973 37.92 12.325 37.944 ;
     RECT  12.181 0.192 12.341 0.552 ;
     RECT  12.157 33.984 12.373 35.88 ;
     RECT  12.373 33.984 12.445 36.312 ;
     RECT  10.78 47.856 12.445 47.88 ;
     RECT  11.405 49.824 12.445 57.624 ;
     RECT  12.445 47.856 12.481 57.624 ;
     RECT  12.341 0.192 12.515 0.456 ;
     RECT  11.845 1.728 12.517 16.392 ;
     RECT  12.445 33.984 12.589 36.504 ;
     RECT  12.325 37.536 12.589 37.944 ;
     RECT  11.549 18.816 12.661 20.952 ;
     RECT  12.265 21.936 12.661 22.872 ;
     RECT  10.643 59.856 12.701 59.88 ;
     RECT  12.517 1.728 12.757 16.584 ;
     RECT  12.661 18.192 12.757 22.872 ;
     RECT  12.589 33.984 12.805 37.944 ;
     RECT  12.277 39.264 12.805 40.152 ;
     RECT  12.515 0.192 12.947 0.36 ;
     RECT  12.757 1.728 13.208 22.872 ;
     RECT  11.873 24.144 13.208 24.168 ;
     RECT  12.193 25.296 13.208 26.808 ;
     RECT  12.161 27.888 13.208 27.912 ;
     RECT  12.913 28.896 13.208 28.92 ;
     RECT  10.793 30.384 13.208 30.408 ;
     RECT  11.765 31.728 13.208 31.752 ;
     RECT  12.805 33.984 13.208 40.152 ;
     RECT  12.025 41.76 13.208 44.088 ;
     RECT  12.908 45.12 13.208 45.144 ;
     RECT  12.481 47.856 13.208 58.152 ;
     RECT  13.208 1.728 13.312 58.332 ;
     RECT  13.312 1.728 13.313 58.152 ;
     RECT  13.313 1.728 13.504 58.104 ;
     RECT  13.504 1.728 13.565 11.736 ;
     RECT  13.504 21.36 13.565 23.88 ;
     RECT  12.947 0.192 13.619 0.312 ;
     RECT  13.504 31.728 13.619 32.76 ;
     RECT  13.504 34.8 13.619 39.336 ;
     RECT  13.504 49.488 13.619 58.104 ;
     RECT  13.565 23.376 13.637 23.88 ;
     RECT  13.619 37.056 13.637 39.336 ;
     RECT  13.619 0.288 13.667 0.312 ;
     RECT  13.504 12.864 13.667 12.888 ;
     RECT  13.637 23.856 13.709 23.88 ;
     RECT  13.619 50.112 13.709 58.104 ;
     RECT  13.504 13.872 13.781 16.296 ;
     RECT  13.504 25.056 13.781 26.808 ;
     RECT  13.709 50.64 14.069 58.104 ;
     RECT  13.504 45.312 14.092 46.104 ;
     RECT  13.781 25.056 14.105 26.664 ;
     RECT  14.069 50.64 14.213 56.808 ;
     RECT  13.619 34.8 14.243 35.928 ;
     RECT  13.637 38.496 14.291 39.336 ;
     RECT  13.637 37.056 14.321 37.512 ;
     RECT  14.291 38.496 14.321 39.288 ;
     RECT  13.504 40.992 14.429 43.032 ;
     RECT  14.213 50.64 14.465 56.472 ;
     RECT  13.504 47.856 14.497 47.88 ;
     RECT  13.504 44.064 14.573 44.088 ;
     RECT  14.465 53.568 14.573 56.472 ;
     RECT  13.619 32.304 14.677 32.328 ;
     RECT  13.565 2.208 14.732 11.736 ;
     RECT  14.732 2.208 14.819 12.312 ;
     RECT  13.781 13.92 14.819 16.296 ;
     RECT  13.565 21.36 14.821 22.344 ;
     RECT  14.573 54.576 14.825 56.472 ;
     RECT  14.465 50.64 14.857 51.144 ;
     RECT  14.749 23.712 14.869 23.736 ;
     RECT  14.465 52.272 14.897 52.44 ;
     RECT  14.069 57.792 14.933 58.104 ;
     RECT  13.504 30.384 14.957 30.408 ;
     RECT  14.869 23.712 14.993 23.976 ;
     RECT  14.105 25.056 14.993 26.52 ;
     RECT  14.957 30.384 15.041 31.32 ;
     RECT  14.821 21.072 15.077 22.488 ;
     RECT  14.993 23.712 15.077 26.52 ;
     RECT  14.819 13.92 15.109 14.952 ;
     RECT  14.092 46.08 15.109 46.104 ;
     RECT  13.504 27.888 15.116 28.488 ;
     RECT  14.857 49.728 15.145 51.144 ;
     RECT  14.677 32.304 15.164 33.144 ;
     RECT  15.109 13.104 15.193 14.952 ;
     RECT  15.116 27.888 15.203 28.68 ;
     RECT  14.897 52.272 15.221 52.296 ;
     RECT  14.825 56.448 15.221 56.472 ;
     RECT  14.243 34.8 15.251 34.824 ;
     RECT  13.504 17.52 15.253 17.64 ;
     RECT  14.321 37.488 15.253 37.512 ;
     RECT  15.145 49.44 15.257 51.144 ;
     RECT  15.077 25.056 15.293 26.52 ;
     RECT  15.253 37.488 15.293 37.608 ;
     RECT  13.504 18.672 15.299 19.848 ;
     RECT  14.933 58.08 15.329 58.104 ;
     RECT  15.257 49.44 15.349 50.616 ;
     RECT  14.819 2.208 15.35 12.024 ;
     RECT  15.164 32.304 15.361 33.528 ;
     RECT  15.349 49.008 15.395 50.616 ;
     RECT  14.819 16.272 15.401 16.296 ;
     RECT  15.109 45.648 15.404 46.104 ;
     RECT  14.497 47.328 15.404 47.88 ;
     RECT  15.395 49.008 15.437 50.568 ;
     RECT  15.299 18.768 15.473 19.848 ;
     RECT  15.293 25.776 15.473 26.52 ;
     RECT  15.404 45.648 15.491 47.88 ;
     RECT  15.445 35.856 15.532 35.88 ;
     RECT  15.491 47.184 15.548 47.88 ;
     RECT  15.548 47.184 15.635 48.408 ;
     RECT  15.193 13.92 15.683 14.952 ;
     RECT  15.473 25.776 15.683 25.8 ;
     RECT  15.35 2.256 15.761 12.024 ;
     RECT  15.473 18.768 15.761 19.656 ;
     RECT  14.321 39.264 15.865 39.288 ;
     RECT  14.429 41.76 15.901 43.032 ;
     RECT  15.683 14.208 15.925 14.952 ;
     RECT  15.541 44.448 15.925 44.472 ;
     RECT  15.491 45.648 15.925 45.672 ;
     RECT  15.635 47.568 15.941 47.88 ;
     RECT  15.925 44.448 15.971 45.672 ;
     RECT  15.761 2.544 15.973 12.024 ;
     RECT  15.901 41.76 16.013 43.08 ;
     RECT  15.077 21.36 16.049 22.488 ;
     RECT  15.437 49.44 16.049 50.568 ;
     RECT  15.041 30.384 16.081 30.408 ;
     RECT  15.293 37.584 16.085 37.608 ;
     RECT  15.971 44.928 16.193 45.144 ;
     RECT  16.013 41.76 16.265 43.032 ;
     RECT  16.265 41.76 16.337 42.744 ;
     RECT  15.077 23.712 16.405 23.976 ;
     RECT  15.865 51.84 16.441 51.864 ;
     RECT  16.049 49.44 16.481 50.184 ;
     RECT  15.865 39.264 16.508 39.336 ;
     RECT  16.081 30.384 16.553 31.224 ;
     RECT  16.508 39.264 16.553 39.72 ;
     RECT  16.553 39.312 16.595 39.72 ;
     RECT  15.761 18.768 16.625 19.512 ;
     RECT  16.049 21.36 16.697 21.672 ;
     RECT  15.925 14.208 16.796 15.912 ;
     RECT  15.973 2.544 16.876 12.888 ;
     RECT  16.625 18.912 16.877 19.512 ;
     RECT  16.796 14.208 16.883 16.248 ;
     RECT  16.877 19.296 16.909 19.512 ;
     RECT  16.876 2.544 16.949 9.144 ;
     RECT  15.361 32.304 16.981 33.624 ;
     RECT  16.981 31.92 17.021 33.624 ;
     RECT  14.825 54.576 17.053 54.6 ;
     RECT  16.949 2.544 17.075 9 ;
     RECT  15.941 47.568 17.089 47.784 ;
     RECT  17.075 3.024 17.123 9 ;
     RECT  16.441 51.84 17.228 52.344 ;
     RECT  17.053 54.576 17.228 55.416 ;
     RECT  16.405 23.328 17.233 23.976 ;
     RECT  15.203 27.888 17.305 28.344 ;
     RECT  16.337 41.76 17.305 42.168 ;
     RECT  17.228 51.264 17.315 52.344 ;
     RECT  17.228 54.576 17.315 55.944 ;
     RECT  17.233 23.04 17.317 23.976 ;
     RECT  17.053 25.104 17.317 25.128 ;
     RECT  16.481 49.44 17.341 50.04 ;
     RECT  17.317 23.04 17.363 25.128 ;
     RECT  17.123 5.136 17.381 9 ;
     RECT  16.193 44.928 17.381 44.952 ;
     RECT  17.305 27.888 17.389 29.112 ;
     RECT  16.883 14.208 17.413 15.912 ;
     RECT  17.341 49.008 17.453 50.04 ;
     RECT  17.317 26.736 17.459 26.76 ;
     RECT  17.089 47.568 17.485 47.88 ;
     RECT  17.315 51.84 17.485 52.344 ;
     RECT  16.876 10.32 17.525 12.888 ;
     RECT  17.525 11.424 17.593 12.888 ;
     RECT  17.413 13.872 17.593 15.912 ;
     RECT  16.553 30.384 17.593 30.408 ;
     RECT  17.363 23.04 17.605 24.936 ;
     RECT  17.381 5.136 17.633 8.904 ;
     RECT  17.021 31.92 17.633 31.944 ;
     RECT  16.909 19.296 17.701 19.8 ;
     RECT  17.605 22.752 17.701 24.936 ;
     RECT  17.389 27.888 17.737 28.344 ;
     RECT  15.253 17.472 18.025 17.64 ;
     RECT  17.123 3.024 18.097 3.864 ;
     RECT  18.025 17.472 18.133 18.264 ;
     RECT  18.133 17.088 18.169 18.264 ;
     RECT  17.701 19.296 18.169 19.944 ;
     RECT  18.169 17.088 18.241 19.944 ;
     RECT  17.593 30.384 18.332 30.744 ;
     RECT  18.332 30.384 18.373 31.368 ;
     RECT  17.485 37.008 18.385 37.032 ;
     RECT  17.737 27.312 18.493 28.344 ;
     RECT  17.305 41.76 18.493 42.696 ;
     RECT  16.405 34.752 18.565 34.776 ;
     RECT  17.485 47.088 18.601 47.88 ;
     RECT  17.453 49.44 18.601 50.04 ;
     RECT  18.097 2.784 18.608 3.864 ;
     RECT  17.633 5.184 18.608 8.904 ;
     RECT  17.525 10.32 18.608 10.44 ;
     RECT  17.593 11.424 18.608 15.912 ;
     RECT  18.241 16.896 18.608 19.944 ;
     RECT  16.697 21.36 18.608 21.624 ;
     RECT  17.701 22.704 18.608 24.936 ;
     RECT  18.493 27.312 18.608 29.064 ;
     RECT  18.373 30.192 18.608 31.368 ;
     RECT  17.021 33.12 18.608 33.624 ;
     RECT  18.565 34.752 18.608 35.016 ;
     RECT  18.385 36.624 18.608 37.032 ;
     RECT  18.457 38.736 18.608 38.76 ;
     RECT  18.493 41.76 18.608 42.792 ;
     RECT  17.881 44.64 18.608 44.76 ;
     RECT  18.601 47.088 18.608 50.04 ;
     RECT  17.485 51.84 18.608 52.44 ;
     RECT  14.573 53.568 18.608 53.592 ;
     RECT  17.315 54.576 18.608 55.416 ;
     RECT  16.765 57.84 18.608 57.864 ;
     RECT  18.608 2.148 18.712 58.332 ;
     RECT  18.712 2.418 18.904 58.062 ;
     RECT  18.904 50.016 19.081 50.76 ;
     RECT  18.904 15.744 19.091 25.128 ;
     RECT  19.081 50.016 19.104 50.04 ;
     RECT  19.091 16.608 19.109 25.128 ;
     RECT  19.109 16.608 19.181 23.976 ;
     RECT  18.904 26.256 19.181 26.616 ;
     RECT  19.181 21.12 19.187 23.976 ;
     RECT  18.904 29.04 19.217 29.064 ;
     RECT  18.904 39.744 19.289 39.768 ;
     RECT  19.109 25.104 19.361 25.128 ;
     RECT  18.904 45.552 19.361 47.112 ;
     RECT  19.181 16.608 19.379 20.04 ;
     RECT  18.904 5.04 19.397 5.832 ;
     RECT  18.904 48.096 19.427 49.032 ;
     RECT  18.904 42.768 19.433 42.792 ;
     RECT  18.904 54.048 19.469 54.072 ;
     RECT  19.181 26.592 19.505 26.616 ;
     RECT  18.904 27.696 19.505 27.72 ;
     RECT  18.904 2.832 19.613 3.864 ;
     RECT  18.904 7.344 19.685 14.76 ;
     RECT  18.904 34.656 19.793 34.776 ;
     RECT  19.187 21.12 19.829 21.144 ;
     RECT  19.793 34.752 19.829 34.776 ;
     RECT  18.904 36 19.829 36.648 ;
     RECT  18.904 30.048 19.937 31.128 ;
     RECT  19.829 36 20.009 36.024 ;
     RECT  19.379 18.72 20.045 20.04 ;
     RECT  19.685 9.024 20.051 14.76 ;
     RECT  19.685 7.344 20.077 7.992 ;
     RECT  18.904 57.264 20.081 57.288 ;
     RECT  20.077 28.128 20.245 28.152 ;
     RECT  18.904 32.448 20.245 33.144 ;
     RECT  18.904 41.76 20.257 41.784 ;
     RECT  20.197 37.584 20.284 37.608 ;
     RECT  18.904 38.736 20.293 38.76 ;
     RECT  20.051 9.168 20.329 14.76 ;
     RECT  20.077 7.056 20.369 7.992 ;
     RECT  20.293 38.736 20.435 39.336 ;
     RECT  20.293 43.872 20.437 43.896 ;
     RECT  20.245 32.448 20.441 33.672 ;
     RECT  20.329 9.168 20.477 14.904 ;
     RECT  20.389 40.56 20.477 40.584 ;
     RECT  19.361 45.552 20.477 46.92 ;
     RECT  19.397 5.136 20.513 5.832 ;
     RECT  20.477 9.744 20.531 14.904 ;
     RECT  20.045 18.72 20.585 19.944 ;
     RECT  20.477 46.128 20.585 46.92 ;
     RECT  20.245 28.128 20.653 28.488 ;
     RECT  19.187 22.176 20.684 22.632 ;
     RECT  20.531 12.48 20.693 14.904 ;
     RECT  20.435 38.736 20.693 38.76 ;
     RECT  20.437 26.064 20.717 26.088 ;
     RECT  19.427 48.096 20.725 48.408 ;
     RECT  20.725 47.28 20.761 48.408 ;
     RECT  20.684 22.176 20.771 22.68 ;
     RECT  19.379 16.608 20.797 17.64 ;
     RECT  20.797 16.608 20.833 17.736 ;
     RECT  20.531 9.744 20.837 11.064 ;
     RECT  20.653 27.888 20.901 28.488 ;
     RECT  19.613 3.6 20.905 3.864 ;
     RECT  19.937 30.384 20.905 31.128 ;
     RECT  20.717 26.064 20.941 26.76 ;
     RECT  19.187 23.664 20.977 23.976 ;
     RECT  20.761 47.28 21.017 48.696 ;
     RECT  20.585 19.296 21.053 19.944 ;
     RECT  20.257 41.616 21.109 41.784 ;
     RECT  20.771 22.176 21.125 22.2 ;
     RECT  20.437 43.872 21.125 44.472 ;
     RECT  20.901 27.888 21.155 27.912 ;
     RECT  21.068 28.944 21.155 28.968 ;
     RECT  21.121 53.616 21.229 53.64 ;
     RECT  21.125 43.872 21.233 43.896 ;
     RECT  20.941 26.064 21.305 26.808 ;
     RECT  20.369 7.056 21.337 7.08 ;
     RECT  21.013 49.68 21.341 49.704 ;
     RECT  21.337 7.056 21.377 7.8 ;
     RECT  20.833 15.984 21.395 17.736 ;
     RECT  20.905 30.24 21.395 31.128 ;
     RECT  20.977 36 21.409 36.024 ;
     RECT  20.905 2.784 21.445 3.864 ;
     RECT  21.305 26.784 21.485 26.808 ;
     RECT  21.445 2.784 21.493 3.912 ;
     RECT  21.229 53.616 21.517 53.832 ;
     RECT  20.441 32.448 21.541 33.144 ;
     RECT  21.517 52.992 21.589 53.832 ;
     RECT  18.904 55.584 21.589 55.608 ;
     RECT  20.837 9.744 21.592 10.344 ;
     RECT  20.585 46.128 21.593 46.152 ;
     RECT  21.517 30.192 21.601 30.216 ;
     RECT  21.541 31.344 21.628 33.144 ;
     RECT  20.693 12.48 21.697 14.856 ;
     RECT  21.395 15.984 21.697 17.4 ;
     RECT  21.053 19.296 21.733 19.32 ;
     RECT  21.628 32.16 21.809 33.144 ;
     RECT  21.589 52.56 21.809 53.832 ;
     RECT  21.017 47.808 21.841 48.696 ;
     RECT  21.377 7.776 21.877 7.8 ;
     RECT  21.592 9.696 21.877 10.344 ;
     RECT  21.697 12.48 21.923 17.4 ;
     RECT  21.493 2.784 21.973 4.536 ;
     RECT  20.513 5.568 21.973 5.832 ;
     RECT  21.877 7.776 21.981 10.344 ;
     RECT  21.981 7.776 22.053 9.288 ;
     RECT  22.053 7.968 22.067 9.288 ;
     RECT  21.733 18.432 22.129 19.32 ;
     RECT  21.661 20.448 22.129 20.472 ;
     RECT  21.109 41.616 22.129 42.168 ;
     RECT  20.977 23.664 22.201 24.552 ;
     RECT  21.841 57.504 22.201 57.528 ;
     RECT  22.129 18.432 22.237 20.472 ;
     RECT  22.237 40.08 22.561 40.104 ;
     RECT  22.201 23.664 22.565 24.6 ;
     RECT  21.877 11.328 22.597 11.352 ;
     RECT  21.923 12.48 22.597 13.704 ;
     RECT  21.589 55.44 22.597 55.608 ;
     RECT  22.201 57.072 22.597 57.528 ;
     RECT  22.597 6.816 22.681 6.84 ;
     RECT  22.067 7.968 22.684 9.24 ;
     RECT  22.597 55.44 22.7 57.528 ;
     RECT  21.733 45.024 22.733 45.048 ;
     RECT  22.733 44.784 22.741 45.048 ;
     RECT  22.561 40.08 22.745 40.2 ;
     RECT  22.7 55.248 22.787 57.528 ;
     RECT  22.741 44.784 22.817 45.576 ;
     RECT  22.787 57.168 22.817 57.528 ;
     RECT  21.981 10.272 22.849 10.344 ;
     RECT  22.597 11.328 22.849 13.704 ;
     RECT  22.237 18.432 22.853 20.856 ;
     RECT  21.625 38.304 22.853 38.328 ;
     RECT  22.745 40.08 22.853 40.104 ;
     RECT  22.129 41.568 22.853 42.168 ;
     RECT  22.787 55.248 22.883 55.944 ;
     RECT  21.409 35.952 22.885 36.024 ;
     RECT  22.817 45.552 22.885 45.576 ;
     RECT  22.237 50.112 22.889 50.136 ;
     RECT  21.923 14.784 22.931 17.4 ;
     RECT  22.931 14.784 22.961 15.336 ;
     RECT  22.849 10.272 23.033 13.704 ;
     RECT  21.841 47.808 23.101 49.08 ;
     RECT  21.973 2.784 23.173 5.832 ;
     RECT  22.931 16.368 23.317 17.4 ;
     RECT  22.853 18.432 23.317 19.32 ;
     RECT  22.885 35.952 23.317 36.072 ;
     RECT  22.885 45.552 23.353 46.152 ;
     RECT  21.809 52.56 23.372 52.584 ;
     RECT  21.809 53.808 23.372 53.832 ;
     RECT  22.237 43.68 23.564 43.704 ;
     RECT  22.684 7.968 23.605 8.52 ;
     RECT  23.564 43.68 23.677 44.424 ;
     RECT  23.317 35.952 23.701 36.504 ;
     RECT  23.033 10.272 23.713 13.608 ;
     RECT  23.317 16.368 23.821 19.32 ;
     RECT  22.853 20.448 23.821 20.856 ;
     RECT  23.353 45.552 23.852 46.776 ;
     RECT  23.101 47.808 23.852 49.896 ;
     RECT  22.883 55.824 23.857 55.944 ;
     RECT  23.677 43.536 23.893 44.424 ;
     RECT  23.852 45.552 23.893 49.896 ;
     RECT  23.173 2.592 24.008 5.832 ;
     RECT  23.605 7.632 24.008 8.52 ;
     RECT  23.713 9.792 24.008 13.608 ;
     RECT  22.961 15.312 24.008 15.336 ;
     RECT  23.821 16.368 24.008 20.856 ;
     RECT  22.565 23.808 24.008 24.6 ;
     RECT  23.893 25.728 24.008 25.752 ;
     RECT  22.705 28.992 24.008 29.016 ;
     RECT  23.641 30.816 24.008 30.84 ;
     RECT  21.809 33.12 24.008 33.144 ;
     RECT  23.461 34.176 24.008 34.2 ;
     RECT  23.701 35.28 24.008 36.504 ;
     RECT  23.101 38.784 24.008 38.808 ;
     RECT  22.853 41.568 24.008 42.024 ;
     RECT  23.893 43.536 24.008 49.896 ;
     RECT  22.849 51.216 24.008 51.24 ;
     RECT  23.372 52.56 24.008 53.832 ;
     RECT  23.857 55.488 24.008 55.944 ;
     RECT  22.817 57.312 24.008 57.528 ;
     RECT  24.008 2.148 24.112 58.332 ;
     RECT  24.112 2.418 24.304 58.062 ;
     RECT  24.304 2.592 24.419 3.96 ;
     RECT  24.304 41.568 24.419 42.168 ;
     RECT  24.304 18.816 24.437 20.664 ;
     RECT  24.304 5.712 24.467 8.52 ;
     RECT  24.304 49.632 24.545 49.896 ;
     RECT  24.304 15.312 24.563 17.4 ;
     RECT  24.419 2.784 24.653 3.96 ;
     RECT  24.437 19.296 24.689 20.664 ;
     RECT  24.304 43.536 24.689 47.064 ;
     RECT  24.689 43.536 24.707 45.288 ;
     RECT  24.304 34.752 24.899 36.456 ;
     RECT  24.653 2.88 24.905 3.96 ;
     RECT  24.899 35.712 24.905 36.456 ;
     RECT  24.304 12 24.941 13.944 ;
     RECT  24.563 15.984 25.049 17.4 ;
     RECT  24.304 10.896 25.085 10.92 ;
     RECT  24.689 20.4 25.121 20.664 ;
     RECT  24.304 28.464 25.187 29.016 ;
     RECT  24.905 35.952 25.193 36.456 ;
     RECT  25.187 28.464 25.229 28.488 ;
     RECT  24.304 38.16 25.235 38.424 ;
     RECT  24.304 39.696 25.235 40.536 ;
     RECT  24.304 56.544 25.301 57.528 ;
     RECT  24.304 52.176 25.369 52.536 ;
     RECT  24.304 53.808 25.369 54.024 ;
     RECT  24.545 49.632 25.373 49.752 ;
     RECT  24.467 7.968 25.513 8.52 ;
     RECT  24.419 41.856 25.513 42.168 ;
     RECT  24.707 43.536 25.513 43.56 ;
     RECT  24.689 46.272 25.513 47.064 ;
     RECT  25.513 46.272 25.517 47.208 ;
     RECT  24.304 23.664 25.553 23.976 ;
     RECT  24.941 12 25.621 12.024 ;
     RECT  24.707 44.736 25.661 45.288 ;
     RECT  25.513 41.856 25.667 43.56 ;
     RECT  25.661 45.264 25.669 45.288 ;
     RECT  25.517 47.184 25.669 47.208 ;
     RECT  25.621 11.904 25.697 12.024 ;
     RECT  25.235 40.368 25.697 40.392 ;
     RECT  25.669 47.184 25.715 47.928 ;
     RECT  24.941 13.008 25.805 13.944 ;
     RECT  25.669 45.264 25.805 46.104 ;
     RECT  25.697 11.904 25.873 11.928 ;
     RECT  24.905 2.88 25.916 3.912 ;
     RECT  25.916 2.88 25.957 3.96 ;
     RECT  25.513 7.92 26.017 8.52 ;
     RECT  24.467 5.712 26.021 6.84 ;
     RECT  24.689 19.296 26.053 19.32 ;
     RECT  25.553 23.952 26.053 23.976 ;
     RECT  24.304 25.152 26.053 25.752 ;
     RECT  26.017 7.92 26.093 9.288 ;
     RECT  26.053 23.952 26.093 25.752 ;
     RECT  25.957 2.832 26.129 3.96 ;
     RECT  26.053 18.816 26.161 19.32 ;
     RECT  25.049 16.704 26.197 17.4 ;
     RECT  26.161 18.816 26.197 19.368 ;
     RECT  25.693 21.648 26.197 21.672 ;
     RECT  25.837 22.8 26.197 22.824 ;
     RECT  26.197 21.648 26.243 22.824 ;
     RECT  26.093 23.952 26.243 25.272 ;
     RECT  25.369 52.176 26.269 54.024 ;
     RECT  25.729 55.584 26.269 55.608 ;
     RECT  26.129 3.36 26.341 3.96 ;
     RECT  26.197 16.704 26.345 19.368 ;
     RECT  25.667 43.536 26.345 43.56 ;
     RECT  25.301 57.504 26.377 57.528 ;
     RECT  25.715 47.904 26.381 47.928 ;
     RECT  25.873 11.52 26.449 11.928 ;
     RECT  26.449 11.376 26.525 11.928 ;
     RECT  26.341 3.36 26.561 4.584 ;
     RECT  25.805 45.264 26.597 45.576 ;
     RECT  26.377 57.024 26.597 57.528 ;
     RECT  26.269 52.176 26.665 55.608 ;
     RECT  26.345 16.704 26.684 18.216 ;
     RECT  26.093 8.304 26.701 9.288 ;
     RECT  26.557 15.072 26.725 15.096 ;
     RECT  26.345 19.296 26.737 19.368 ;
     RECT  25.121 20.4 26.737 20.616 ;
     RECT  26.725 14.928 26.771 15.096 ;
     RECT  26.684 16.128 26.771 18.216 ;
     RECT  25.805 13.008 26.773 13.032 ;
     RECT  26.243 21.84 26.773 22.824 ;
     RECT  26.243 23.952 26.773 24.264 ;
     RECT  26.665 52.176 26.773 55.992 ;
     RECT  26.773 21.84 26.777 24.264 ;
     RECT  26.737 19.296 26.813 20.616 ;
     RECT  26.701 8.304 26.849 9.576 ;
     RECT  26.771 16.656 26.885 18.216 ;
     RECT  26.243 25.248 26.885 25.272 ;
     RECT  26.777 22.704 26.921 24.264 ;
     RECT  26.921 23.28 26.957 24.264 ;
     RECT  26.773 52.176 26.993 56.808 ;
     RECT  26.849 9.072 27.209 9.576 ;
     RECT  26.993 53.808 27.209 56.808 ;
     RECT  26.773 12.864 27.212 13.032 ;
     RECT  26.771 14.928 27.212 14.952 ;
     RECT  26.525 11.376 27.245 11.88 ;
     RECT  25.373 49.632 27.245 49.656 ;
     RECT  26.561 3.648 27.277 4.584 ;
     RECT  26.021 5.808 27.277 6.84 ;
     RECT  27.209 55.584 27.281 56.808 ;
     RECT  27.245 11.568 27.299 11.88 ;
     RECT  27.212 12.864 27.299 14.952 ;
     RECT  26.597 45.264 27.349 45.288 ;
     RECT  27.281 56.784 27.353 56.808 ;
     RECT  27.277 3.648 27.389 6.84 ;
     RECT  27.313 26.784 27.425 26.808 ;
     RECT  27.349 45.024 27.433 45.288 ;
     RECT  25.235 38.4 27.457 38.424 ;
     RECT  26.813 20.544 27.491 20.616 ;
     RECT  27.281 55.584 27.497 55.704 ;
     RECT  27.389 4.944 27.589 6.84 ;
     RECT  27.589 4.944 27.635 7.368 ;
     RECT  27.457 38.4 27.641 38.76 ;
     RECT  27.635 4.944 27.677 6.024 ;
     RECT  26.957 23.28 27.713 23.976 ;
     RECT  25.193 35.952 27.788 36.072 ;
     RECT  27.389 3.648 27.853 3.96 ;
     RECT  26.885 16.656 27.853 17.4 ;
     RECT  27.788 35.952 27.875 36.744 ;
     RECT  27.853 43.296 27.973 43.32 ;
     RECT  27.853 16.656 27.997 18.216 ;
     RECT  27.433 45.264 28.019 45.288 ;
     RECT  27.973 43.296 28.06 44.28 ;
     RECT  27.299 12.864 28.105 13.32 ;
     RECT  27.299 11.568 28.109 11.832 ;
     RECT  27.299 14.832 28.181 14.856 ;
     RECT  27.875 35.952 28.181 36.36 ;
     RECT  27.421 10.56 28.213 10.584 ;
     RECT  27.209 53.808 28.22 53.832 ;
     RECT  27.209 9.072 28.253 9.096 ;
     RECT  28.213 10.56 28.253 10.728 ;
     RECT  28.105 49.872 28.261 49.896 ;
     RECT  26.993 52.176 28.261 52.2 ;
     RECT  28.261 48.96 28.307 49.896 ;
     RECT  28.22 53.184 28.307 53.832 ;
     RECT  25.667 41.856 28.321 42.168 ;
     RECT  28.06 43.296 28.321 43.32 ;
     RECT  27.709 40.368 28.361 40.392 ;
     RECT  24.304 33.12 28.393 33.144 ;
     RECT  28.213 34.752 28.393 34.776 ;
     RECT  27.497 55.68 28.465 55.704 ;
     RECT  27.491 20.592 28.501 20.616 ;
     RECT  28.285 30.816 28.537 30.84 ;
     RECT  27.385 32.112 28.537 32.136 ;
     RECT  27.997 15.936 28.549 18.216 ;
     RECT  26.813 19.296 28.549 19.512 ;
     RECT  28.321 41.856 28.604 43.32 ;
     RECT  28.307 48.96 28.645 48.984 ;
     RECT  28.307 53.568 28.681 53.832 ;
     RECT  28.465 55.488 28.681 55.704 ;
     RECT  28.537 30.816 28.717 32.136 ;
     RECT  27.853 3.36 28.825 3.96 ;
     RECT  28.105 12.816 28.897 13.32 ;
     RECT  28.825 3.12 28.933 3.96 ;
     RECT  27.641 38.4 28.933 38.424 ;
     RECT  28.933 57.216 29.005 57.24 ;
     RECT  28.501 20.592 29.029 21.384 ;
     RECT  28.717 30.72 29.077 32.136 ;
     RECT  28.393 33.12 29.077 34.776 ;
     RECT  29.077 30.72 29.113 34.776 ;
     RECT  29.005 57.216 29.113 57.432 ;
     RECT  28.537 47.328 29.257 47.448 ;
     RECT  28.933 2.88 29.329 3.96 ;
     RECT  27.677 5.232 29.329 6.024 ;
     RECT  29.113 57.12 29.365 57.432 ;
     RECT  28.261 51.744 29.401 52.2 ;
     RECT  29.329 2.88 29.408 6.024 ;
     RECT  27.635 7.344 29.408 7.368 ;
     RECT  28.861 8.544 29.408 8.568 ;
     RECT  28.253 10.704 29.408 10.728 ;
     RECT  28.897 11.952 29.408 13.32 ;
     RECT  28.549 15.936 29.408 19.512 ;
     RECT  29.029 20.496 29.408 21.384 ;
     RECT  27.713 23.952 29.408 23.976 ;
     RECT  29.113 30.72 29.408 34.824 ;
     RECT  28.181 36.336 29.408 36.36 ;
     RECT  28.933 37.44 29.408 38.424 ;
     RECT  28.604 41.04 29.408 43.32 ;
     RECT  29.257 46.8 29.408 47.448 ;
     RECT  28.645 48.672 29.408 48.984 ;
     RECT  29.401 51.168 29.408 52.2 ;
     RECT  28.681 53.568 29.408 55.704 ;
     RECT  29.365 57.072 29.408 57.432 ;
     RECT  29.408 2.148 29.512 58.332 ;
     RECT  29.512 2.418 29.704 58.062 ;
     RECT  29.704 17.088 29.801 19.32 ;
     RECT  29.704 30.048 29.801 31.176 ;
     RECT  29.704 51.168 29.873 52.2 ;
     RECT  29.704 3.12 29.904 8.568 ;
     RECT  29.704 10.128 29.945 13.32 ;
     RECT  29.704 32.448 30.017 35.064 ;
     RECT  29.801 17.088 30.089 17.688 ;
     RECT  29.945 10.128 30.131 11.4 ;
     RECT  30.017 33.12 30.161 35.064 ;
     RECT  30.131 10.128 30.197 10.728 ;
     RECT  29.704 41.04 30.197 43.32 ;
     RECT  29.873 51.744 30.197 52.2 ;
     RECT  29.704 57.024 30.233 57.336 ;
     RECT  29.904 3.12 30.269 8.328 ;
     RECT  29.704 26.592 30.269 26.856 ;
     RECT  29.704 37.44 30.305 37.464 ;
     RECT  29.704 53.808 30.377 54.648 ;
     RECT  29.801 19.248 30.449 19.32 ;
     RECT  30.197 41.04 30.457 42.792 ;
     RECT  30.269 5.808 30.467 8.328 ;
     RECT  29.704 14.4 30.515 16.008 ;
     RECT  29.704 36.336 30.515 36.36 ;
     RECT  30.269 26.64 30.521 26.856 ;
     RECT  30.515 14.4 30.556 14.664 ;
     RECT  30.521 26.736 30.557 26.856 ;
     RECT  29.704 38.64 30.557 38.664 ;
     RECT  30.233 57.12 30.557 57.336 ;
     RECT  29.945 12.768 30.593 13.32 ;
     RECT  29.801 30.72 30.593 31.176 ;
     RECT  30.269 3.12 30.737 4.68 ;
     RECT  30.557 26.832 30.737 26.856 ;
     RECT  29.704 20.592 30.805 20.904 ;
     RECT  30.467 7.92 30.809 8.328 ;
     RECT  30.593 30.96 30.809 31.176 ;
     RECT  30.457 41.04 30.809 42.024 ;
     RECT  29.704 55.776 30.845 55.8 ;
     RECT  30.805 19.776 30.851 20.904 ;
     RECT  30.089 17.088 30.881 17.112 ;
     RECT  30.161 33.12 30.953 34.104 ;
     RECT  30.197 52.176 30.989 52.2 ;
     RECT  30.809 8.304 31.237 8.328 ;
     RECT  30.197 10.128 31.237 10.152 ;
     RECT  29.704 46.32 31.309 47.832 ;
     RECT  30.515 15.984 31.313 16.008 ;
     RECT  31.237 8.304 31.493 10.152 ;
     RECT  31.309 46.224 31.493 47.832 ;
     RECT  31.493 46.32 31.529 47.832 ;
     RECT  30.809 41.616 31.715 42.024 ;
     RECT  31.715 42 31.717 42.024 ;
     RECT  31.489 18.768 31.741 18.792 ;
     RECT  31.493 9.072 31.745 10.152 ;
     RECT  31.669 39.888 31.772 39.912 ;
     RECT  30.557 57.12 31.777 57.144 ;
     RECT  31.717 42 31.813 42.12 ;
     RECT  31.772 39.648 31.859 39.912 ;
     RECT  30.737 3.12 31.889 4.536 ;
     RECT  30.985 49.008 31.921 49.032 ;
     RECT  31.633 44.448 31.957 44.472 ;
     RECT  30.809 30.96 31.961 30.984 ;
     RECT  31.813 42 31.961 42.216 ;
     RECT  30.467 6.816 31.993 6.84 ;
     RECT  31.921 49.008 31.993 49.176 ;
     RECT  31.777 57.024 31.993 57.144 ;
     RECT  31.529 47.04 32.029 47.832 ;
     RECT  31.993 48.912 32.068 49.176 ;
     RECT  31.957 43.824 32.099 44.52 ;
     RECT  30.593 12.768 32.101 12.936 ;
     RECT  30.377 53.808 32.101 54.072 ;
     RECT  31.921 51.936 32.137 51.96 ;
     RECT  32.101 53.808 32.137 54.168 ;
     RECT  31.961 42 32.14 42.168 ;
     RECT  30.467 5.808 32.209 5.832 ;
     RECT  30.851 19.776 32.209 20.616 ;
     RECT  31.453 22.224 32.209 22.248 ;
     RECT  31.745 9.072 32.249 9.24 ;
     RECT  32.101 12.768 32.317 13.032 ;
     RECT  32.068 48.912 32.317 49.224 ;
     RECT  30.556 14.64 32.341 14.664 ;
     RECT  32.281 17.088 32.341 17.112 ;
     RECT  32.029 47.04 32.353 47.88 ;
     RECT  32.317 48.912 32.353 49.512 ;
     RECT  32.137 51.936 32.357 54.168 ;
     RECT  31.993 57.024 32.389 57.528 ;
     RECT  32.353 47.04 32.393 49.512 ;
     RECT  29.704 23.952 32.425 23.976 ;
     RECT  32.341 15.888 32.429 17.112 ;
     RECT  32.389 56.976 32.429 57.528 ;
     RECT  31.741 18.576 32.497 18.792 ;
     RECT  32.209 19.776 32.497 22.248 ;
     RECT  32.393 49.2 32.501 49.512 ;
     RECT  32.497 18.576 32.573 22.248 ;
     RECT  31.993 6.816 32.605 7.416 ;
     RECT  32.573 18.576 32.609 22.152 ;
     RECT  32.389 35.856 32.641 35.88 ;
     RECT  32.501 49.2 32.642 49.32 ;
     RECT  31.889 3.12 32.669 3.96 ;
     RECT  32.357 52.464 32.681 54.168 ;
     RECT  32.669 2.736 32.716 3.96 ;
     RECT  32.317 12 32.749 13.032 ;
     RECT  32.681 52.512 32.789 54.168 ;
     RECT  32.249 9.216 32.821 9.24 ;
     RECT  32.341 14.64 32.857 14.856 ;
     RECT  32.642 49.2 32.897 49.272 ;
     RECT  32.609 20.304 33.005 22.152 ;
     RECT  32.897 49.248 33.005 49.272 ;
     RECT  32.641 35.856 33.113 35.976 ;
     RECT  32.425 40.224 33.113 40.248 ;
     RECT  33.037 31.152 33.149 31.176 ;
     RECT  33.113 35.952 33.149 35.976 ;
     RECT  30.953 33.12 33.253 33.144 ;
     RECT  32.609 18.576 33.325 19.032 ;
     RECT  32.789 52.992 33.325 54.168 ;
     RECT  32.605 6.816 33.329 7.752 ;
     RECT  33.181 34.656 33.365 34.68 ;
     RECT  31.669 38.64 33.469 38.664 ;
     RECT  33.469 38.64 33.505 39.336 ;
     RECT  33.253 33.12 33.509 33.432 ;
     RECT  32.821 9.216 33.541 9.576 ;
     RECT  32.429 56.976 33.545 57.048 ;
     RECT  33.541 8.304 33.577 9.576 ;
     RECT  33.505 38.496 33.577 39.336 ;
     RECT  33.325 52.992 33.653 54.648 ;
     RECT  32.099 43.824 33.757 43.848 ;
     RECT  32.14 42 33.829 42.024 ;
     RECT  33.613 29.04 33.833 29.064 ;
     RECT  32.393 47.04 33.865 48.024 ;
     RECT  32.749 11.808 33.937 13.032 ;
     RECT  33.005 20.352 33.937 22.152 ;
     RECT  33.937 11.808 34.117 13.608 ;
     RECT  32.857 14.64 34.117 15.336 ;
     RECT  32.429 16.368 34.117 17.112 ;
     RECT  33.865 46.752 34.161 48.024 ;
     RECT  33.577 38.16 34.165 39.336 ;
     RECT  33.653 53.808 34.175 54.648 ;
     RECT  34.175 53.808 34.213 54.696 ;
     RECT  33.937 55.824 34.213 55.848 ;
     RECT  33.545 56.976 34.213 57 ;
     RECT  34.161 46.752 34.261 48.36 ;
     RECT  34.045 36.432 34.333 36.456 ;
     RECT  33.829 41.04 34.333 42.024 ;
     RECT  33.757 43.248 34.333 43.848 ;
     RECT  34.333 35.712 34.549 36.456 ;
     RECT  34.165 38.16 34.549 39.528 ;
     RECT  34.333 41.04 34.549 43.848 ;
     RECT  34.261 46.704 34.549 48.36 ;
     RECT  32.209 5.664 34.585 5.832 ;
     RECT  33.329 6.816 34.585 6.84 ;
     RECT  34.549 35.712 34.585 37.032 ;
     RECT  34.213 53.808 34.645 57 ;
     RECT  32.425 23.952 34.693 24.024 ;
     RECT  33.901 51.264 34.693 51.288 ;
     RECT  34.357 52.656 34.693 52.68 ;
     RECT  34.645 53.808 34.693 57.624 ;
     RECT  33.577 8.304 34.801 10.536 ;
     RECT  34.333 26.208 34.801 26.232 ;
     RECT  32.716 2.736 34.808 3.864 ;
     RECT  34.585 5.664 34.808 6.84 ;
     RECT  34.801 7.968 34.808 10.536 ;
     RECT  34.117 11.808 34.808 17.112 ;
     RECT  33.325 18.432 34.808 19.032 ;
     RECT  33.937 20.352 34.808 22.824 ;
     RECT  34.693 23.952 34.808 24.504 ;
     RECT  34.801 26.112 34.808 26.232 ;
     RECT  34.801 30.576 34.808 30.6 ;
     RECT  33.509 33.12 34.808 33.144 ;
     RECT  34.585 35.424 34.808 37.032 ;
     RECT  34.549 38.16 34.808 43.848 ;
     RECT  34.549 45.648 34.808 48.36 ;
     RECT  34.045 49.344 34.808 49.368 ;
     RECT  34.693 51.264 34.808 52.776 ;
     RECT  34.693 53.808 34.808 57.72 ;
     RECT  34.808 2.148 34.912 58.332 ;
     RECT  34.912 2.418 35.104 58.062 ;
     RECT  35.104 51.936 35.201 52.776 ;
     RECT  35.104 30.24 35.219 31.368 ;
     RECT  35.104 33.12 35.219 41.016 ;
     RECT  35.104 42 35.219 43.848 ;
     RECT  35.104 18.72 35.363 20.616 ;
     RECT  35.363 20.352 35.381 20.616 ;
     RECT  35.104 46.752 35.417 48.216 ;
     RECT  35.219 42.672 35.561 43.848 ;
     RECT  35.417 46.752 35.561 47.736 ;
     RECT  35.104 56.352 35.597 56.376 ;
     RECT  35.201 52.752 35.633 52.776 ;
     RECT  35.219 35.424 35.651 37.608 ;
     RECT  35.104 7.968 35.705 7.992 ;
     RECT  35.651 35.424 35.705 36.936 ;
     RECT  35.219 38.592 35.74 41.016 ;
     RECT  35.104 17.088 35.741 17.496 ;
     RECT  35.104 4.944 35.747 6.888 ;
     RECT  35.104 11.28 35.747 12.504 ;
     RECT  35.104 13.68 35.747 15.768 ;
     RECT  35.747 6.816 35.749 6.888 ;
     RECT  35.104 57.696 35.813 57.72 ;
     RECT  35.104 45.6 35.843 45.624 ;
     RECT  35.705 35.424 35.849 36.6 ;
     RECT  35.74 39.936 35.857 41.016 ;
     RECT  35.104 2.64 35.939 3.96 ;
     RECT  35.104 49.872 35.939 50.712 ;
     RECT  35.104 23.952 35.957 24.504 ;
     RECT  35.857 39.936 35.957 40.056 ;
     RECT  35.561 42.768 35.993 43.848 ;
     RECT  35.747 11.28 36.029 12.36 ;
     RECT  35.219 33.12 36.029 33.912 ;
     RECT  35.561 46.752 36.065 47.304 ;
     RECT  35.747 15.168 36.097 15.768 ;
     RECT  36.097 15.168 36.137 15.96 ;
     RECT  35.939 2.64 36.173 2.952 ;
     RECT  35.957 39.936 36.173 40.008 ;
     RECT  35.993 42.768 36.173 43.368 ;
     RECT  35.104 27.36 36.209 28.68 ;
     RECT  35.747 13.68 36.317 13.992 ;
     RECT  35.849 36.576 36.317 36.6 ;
     RECT  36.029 11.28 36.353 12.12 ;
     RECT  36.137 15.744 36.353 15.96 ;
     RECT  35.939 3.936 36.389 3.96 ;
     RECT  35.747 4.944 36.389 5.832 ;
     RECT  36.065 47.04 36.389 47.304 ;
     RECT  36.029 33.888 36.517 33.912 ;
     RECT  35.957 24.48 36.529 24.504 ;
     RECT  36.449 53.04 36.533 53.064 ;
     RECT  35.381 20.448 36.565 20.616 ;
     RECT  36.529 24.48 36.565 24.888 ;
     RECT  35.104 26.112 36.565 26.136 ;
     RECT  35.363 18.72 36.593 19.32 ;
     RECT  36.517 32.88 36.605 32.904 ;
     RECT  35.74 38.592 36.605 38.76 ;
     RECT  36.209 27.36 36.611 28.488 ;
     RECT  36.593 18.672 36.677 19.32 ;
     RECT  36.389 47.28 36.677 47.304 ;
     RECT  35.104 54.096 36.677 54.696 ;
     RECT  36.389 5.664 36.709 5.832 ;
     RECT  35.749 6.816 36.709 6.84 ;
     RECT  36.709 5.664 36.755 6.84 ;
     RECT  36.565 20.448 36.755 20.76 ;
     RECT  36.565 24.48 36.781 26.136 ;
     RECT  35.219 30.24 36.817 30.264 ;
     RECT  35.939 50.688 36.817 50.712 ;
     RECT  36.277 52.032 36.817 52.056 ;
     RECT  36.353 12.096 36.821 12.12 ;
     RECT  36.755 20.448 36.821 20.568 ;
     RECT  36.611 27.936 36.821 28.488 ;
     RECT  36.817 50.688 36.901 52.056 ;
     RECT  36.781 24.48 36.961 26.808 ;
     RECT  36.817 30.24 36.961 30.504 ;
     RECT  36.173 2.88 36.965 2.952 ;
     RECT  35.741 17.088 36.997 17.448 ;
     RECT  36.755 5.664 37.001 6.264 ;
     RECT  36.517 33.888 37.001 34.344 ;
     RECT  36.961 23.904 37.005 26.808 ;
     RECT  36.173 39.984 37.045 40.008 ;
     RECT  36.853 41.616 37.045 41.64 ;
     RECT  37.005 23.808 37.091 26.808 ;
     RECT  37.045 39.984 37.091 41.64 ;
     RECT  36.965 2.928 37.109 2.952 ;
     RECT  37.091 25.104 37.129 26.136 ;
     RECT  37.091 39.984 37.145 41.16 ;
     RECT  36.709 10.272 37.177 10.296 ;
     RECT  36.173 42.768 37.213 42.792 ;
     RECT  37.148 12.912 37.235 12.936 ;
     RECT  36.821 28.464 37.249 28.488 ;
     RECT  36.821 20.544 37.253 20.568 ;
     RECT  37.213 42.528 37.253 42.792 ;
     RECT  36.961 30.24 37.325 30.744 ;
     RECT  36.901 50.688 37.361 50.712 ;
     RECT  36.817 38.4 37.393 38.424 ;
     RECT  36.997 17.088 37.433 17.64 ;
     RECT  37.249 28.464 37.465 29.064 ;
     RECT  36.961 56.4 37.573 56.424 ;
     RECT  36.601 57.84 37.573 57.864 ;
     RECT  37.357 22.752 37.619 22.776 ;
     RECT  37.001 33.888 37.649 34.104 ;
     RECT  36.997 9.12 37.681 9.144 ;
     RECT  37.573 56.4 37.681 57.864 ;
     RECT  37.681 55.728 37.685 57.864 ;
     RECT  36.353 15.936 37.717 15.96 ;
     RECT  37.433 17.088 37.717 17.112 ;
     RECT  37.717 15.936 37.757 17.112 ;
     RECT  36.317 13.968 37.829 13.992 ;
     RECT  37.393 37.584 37.865 38.424 ;
     RECT  37.825 12.384 37.897 12.408 ;
     RECT  36.817 48.288 37.937 48.312 ;
     RECT  36.677 54.672 37.964 54.696 ;
     RECT  37.964 54.528 37.969 54.696 ;
     RECT  37.685 55.728 37.969 57.576 ;
     RECT  37.145 41.136 38.009 41.16 ;
     RECT  36.677 18.768 38.113 19.272 ;
     RECT  37.091 23.808 38.113 23.928 ;
     RECT  37.757 15.936 38.189 16.536 ;
     RECT  36.901 52.032 38.197 52.056 ;
     RECT  37.969 54.528 38.197 57.576 ;
     RECT  38.005 47.28 38.225 47.304 ;
     RECT  37.649 34.08 38.297 34.104 ;
     RECT  35.849 35.424 38.329 35.448 ;
     RECT  38.113 23.376 38.333 23.928 ;
     RECT  38.197 54.096 38.333 57.576 ;
     RECT  37.393 32.16 38.365 32.184 ;
     RECT  37.609 50.16 38.401 50.28 ;
     RECT  38.197 52.032 38.405 53.016 ;
     RECT  38.333 54.096 38.441 56.424 ;
     RECT  37.465 28.464 38.509 29.448 ;
     RECT  38.473 21.36 38.545 21.384 ;
     RECT  37.325 30.48 38.545 30.6 ;
     RECT  38.545 30.48 38.585 30.984 ;
     RECT  38.333 23.376 38.621 23.88 ;
     RECT  38.441 54.096 38.689 54.12 ;
     RECT  38.689 54.048 38.69 54.12 ;
     RECT  37.253 42.528 38.725 42.552 ;
     RECT  37.933 4.416 38.761 4.44 ;
     RECT  38.509 28.416 38.765 29.448 ;
     RECT  38.725 42.528 38.765 43.368 ;
     RECT  38.257 6.864 38.773 6.888 ;
     RECT  37.177 10.272 38.773 10.872 ;
     RECT  37.897 12.336 38.773 12.408 ;
     RECT  38.773 10.272 38.797 12.408 ;
     RECT  38.689 13.92 38.797 13.944 ;
     RECT  38.185 48.432 38.797 48.456 ;
     RECT  38.041 39.744 38.819 39.768 ;
     RECT  38.797 10.272 38.837 13.944 ;
     RECT  38.773 6.864 38.86 7.464 ;
     RECT  37.681 8.448 38.86 9.144 ;
     RECT  38.837 10.272 38.86 11.64 ;
     RECT  38.329 35.328 38.869 35.448 ;
     RECT  38.86 10.272 38.873 10.92 ;
     RECT  38.765 28.464 38.873 29.448 ;
     RECT  38.401 50.16 38.873 50.712 ;
     RECT  37.129 25.104 38.904 25.272 ;
     RECT  38.873 10.896 38.945 10.92 ;
     RECT  38.904 25.104 38.965 25.368 ;
     RECT  38.545 26.688 38.965 26.712 ;
     RECT  38.797 48.432 38.965 48.984 ;
     RECT  38.965 25.104 39.011 26.952 ;
     RECT  38.873 28.464 39.011 29.112 ;
     RECT  38.965 47.856 39.011 48.984 ;
     RECT  38.189 16.512 39.017 16.536 ;
     RECT  37.285 45.6 39.049 45.624 ;
     RECT  39.011 28.464 39.053 28.488 ;
     RECT  39.011 47.856 39.053 47.88 ;
     RECT  38.405 52.032 39.053 52.68 ;
     RECT  38.545 21.36 39.068 21.432 ;
     RECT  38.86 6.864 39.085 6.888 ;
     RECT  38.113 18.192 39.109 19.272 ;
     RECT  37.865 37.584 39.121 37.608 ;
     RECT  39.068 20.544 39.155 21.432 ;
     RECT  39.121 37.056 39.157 37.608 ;
     RECT  39.053 52.656 39.161 52.68 ;
     RECT  39.011 25.104 39.197 25.896 ;
     RECT  38.149 41.088 39.212 41.112 ;
     RECT  38.873 50.688 39.229 50.712 ;
     RECT  39.085 6.624 39.233 6.888 ;
     RECT  38.581 38.688 39.253 38.712 ;
     RECT  38.837 13.056 39.301 13.944 ;
     RECT  38.365 32.16 39.301 32.856 ;
     RECT  39.011 48.96 39.301 48.984 ;
     RECT  39.013 2.736 39.337 2.76 ;
     RECT  38.869 34.56 39.349 35.448 ;
     RECT  39.157 36.768 39.349 37.608 ;
     RECT  38.441 56.16 39.445 56.424 ;
     RECT  38.333 57.552 39.445 57.576 ;
     RECT  38.621 23.808 39.769 23.88 ;
     RECT  38.761 4.416 39.869 4.824 ;
     RECT  39.337 2.736 39.877 2.856 ;
     RECT  39.049 45.6 39.877 46.536 ;
     RECT  38.765 43.344 39.884 43.368 ;
     RECT  39.733 16.944 39.925 16.968 ;
     RECT  39.212 40.416 39.949 41.112 ;
     RECT  39.229 50.688 39.985 50.904 ;
     RECT  39.949 40.176 40.021 41.112 ;
     RECT  39.011 26.928 40.057 26.952 ;
     RECT  39.884 42.48 40.129 43.368 ;
     RECT  39.877 2.736 40.208 3.192 ;
     RECT  39.869 4.416 40.208 5.16 ;
     RECT  39.233 6.624 40.208 6.648 ;
     RECT  38.86 9.12 40.208 9.144 ;
     RECT  39.301 13.056 40.208 14.232 ;
     RECT  38.977 15.408 40.208 15.432 ;
     RECT  39.925 16.944 40.208 17.112 ;
     RECT  39.109 18.192 40.208 19.368 ;
     RECT  39.155 21.408 40.208 21.432 ;
     RECT  38.905 22.464 40.208 22.488 ;
     RECT  39.769 23.808 40.208 24.696 ;
     RECT  39.197 25.872 40.208 25.896 ;
     RECT  40.057 26.928 40.208 27.912 ;
     RECT  38.585 30.816 40.208 30.984 ;
     RECT  39.301 32.16 40.208 33.048 ;
     RECT  39.349 34.56 40.208 37.608 ;
     RECT  39.253 38.688 40.208 38.904 ;
     RECT  40.021 39.888 40.208 41.112 ;
     RECT  40.129 42.48 40.208 43.656 ;
     RECT  39.877 45.6 40.208 47.4 ;
     RECT  39.301 48.96 40.208 49.368 ;
     RECT  39.985 50.688 40.208 51 ;
     RECT  38.69 54.048 40.208 54.072 ;
     RECT  39.445 56.16 40.208 57.576 ;
     RECT  40.208 2.148 40.312 58.332 ;
     RECT  40.312 2.418 40.504 58.062 ;
     RECT  40.504 3.312 40.637 3.336 ;
     RECT  40.504 52.56 40.637 52.584 ;
    LAYER M5 ;
     RECT  9.024 0.144 13.512 0.181 ;
     RECT  9.024 0.181 13.608 0.277 ;
     RECT  9.024 0.277 13.656 1.763 ;
     RECT  2.4 2.137 2.52 2.151 ;
     RECT  7.8 2.137 7.92 2.151 ;
     RECT  18.6 2.137 18.72 2.151 ;
     RECT  24 2.137 24.12 2.151 ;
     RECT  29.4 2.137 29.52 2.151 ;
     RECT  34.8 2.137 34.92 2.151 ;
     RECT  40.2 2.137 40.32 2.151 ;
     RECT  10.176 1.763 13.656 2.197 ;
     RECT  7.8 2.151 8.112 2.245 ;
     RECT  10.176 2.197 14.232 2.245 ;
     RECT  24 2.151 24.312 2.581 ;
     RECT  34.8 2.151 35.112 2.629 ;
     RECT  2.4 2.151 2.712 2.773 ;
     RECT  2.4 2.773 3.624 2.821 ;
     RECT  18.6 2.151 18.912 2.821 ;
     RECT  40.2 2.151 40.512 2.821 ;
     RECT  2.4 2.821 4.152 2.869 ;
     RECT  2.304 2.869 4.152 2.963 ;
     RECT  6.864 2.245 8.112 3.061 ;
     RECT  5.184 2.821 5.208 3.109 ;
     RECT  18.6 2.821 19.56 3.155 ;
     RECT  32.688 2.725 32.712 3.157 ;
     RECT  39.984 2.821 40.512 3.157 ;
     RECT  32.544 3.157 32.712 3.203 ;
     RECT  32.544 3.203 32.664 3.299 ;
     RECT  17.04 2.533 17.064 3.349 ;
     RECT  16.848 3.349 17.064 3.395 ;
     RECT  10.176 2.245 15.384 3.539 ;
     RECT  18.6 3.155 19.416 3.635 ;
     RECT  5.136 3.109 5.208 3.877 ;
     RECT  6.336 3.061 8.112 3.877 ;
     RECT  23.184 2.581 24.408 3.925 ;
     RECT  34.8 2.629 35.928 3.971 ;
     RECT  5.136 3.877 8.112 4.019 ;
     RECT  10.176 3.539 15.192 4.019 ;
     RECT  5.184 4.019 8.112 4.115 ;
     RECT  22.032 3.877 22.056 4.117 ;
     RECT  21.984 4.117 22.056 4.501 ;
     RECT  5.424 4.115 8.112 4.645 ;
     RECT  16.848 3.395 16.872 4.645 ;
     RECT  5.424 4.645 8.232 5.027 ;
     RECT  7.2 5.027 8.232 5.029 ;
     RECT  18.6 3.635 18.912 5.029 ;
     RECT  16.848 4.645 17.112 5.171 ;
     RECT  39.888 3.157 40.512 5.171 ;
     RECT  5.424 5.027 5.88 5.173 ;
     RECT  10.704 4.019 15.192 5.173 ;
     RECT  2.304 2.963 3.624 5.219 ;
     RECT  23.184 3.925 24.552 5.459 ;
     RECT  2.4 5.219 3.624 5.507 ;
     RECT  18.6 5.029 19.32 5.603 ;
     RECT  21.504 4.501 22.056 5.603 ;
     RECT  34.8 3.971 35.112 5.653 ;
     RECT  32.64 3.299 32.664 5.699 ;
     RECT  18.6 5.603 18.912 5.701 ;
     RECT  25.968 2.821 25.992 5.747 ;
     RECT  7.2 5.029 8.28 5.989 ;
     RECT  29.4 2.151 29.712 5.989 ;
     RECT  7.2 5.989 8.328 6.085 ;
     RECT  10.416 5.173 15.192 6.323 ;
     RECT  18.24 5.701 18.912 6.323 ;
     RECT  10.416 6.323 15.096 6.371 ;
     RECT  24 5.459 24.552 6.707 ;
     RECT  9.408 4.501 9.432 6.709 ;
     RECT  10.416 6.371 15 6.709 ;
     RECT  29.4 5.989 30.12 6.757 ;
     RECT  21.984 5.603 22.056 6.805 ;
     RECT  5.376 5.173 5.88 6.899 ;
     RECT  34.8 5.653 35.736 6.899 ;
     RECT  7.2 6.085 8.376 7.045 ;
     RECT  16.848 5.171 16.872 7.091 ;
     RECT  6.768 7.045 8.376 7.285 ;
     RECT  9.408 6.709 15 7.285 ;
     RECT  18.6 6.323 18.912 7.333 ;
     RECT  27.6 5.605 27.624 7.379 ;
     RECT  6.768 7.285 15 7.381 ;
     RECT  6.768 7.381 15.144 7.427 ;
     RECT  38.784 6.853 38.808 7.475 ;
     RECT  24 6.707 24.456 7.621 ;
     RECT  23.616 7.621 24.456 7.667 ;
     RECT  2.4 5.507 2.712 7.813 ;
     RECT  7.2 7.427 15.144 7.907 ;
     RECT  2.4 7.813 2.856 7.909 ;
     RECT  29.4 6.757 30.456 7.955 ;
     RECT  18.6 7.333 19.176 7.957 ;
     RECT  7.2 7.907 13.608 8.003 ;
     RECT  2.304 7.909 2.952 8.195 ;
     RECT  21.984 6.805 22.632 8.245 ;
     RECT  16.416 7.861 16.44 8.485 ;
     RECT  34.8 6.899 35.112 8.869 ;
     RECT  7.2 8.003 13.512 8.963 ;
     RECT  18.6 7.957 19.992 9.013 ;
     RECT  38.784 8.437 38.808 9.155 ;
     RECT  21.936 8.245 22.632 9.251 ;
     RECT  21.936 9.251 22.056 9.299 ;
     RECT  16.416 8.485 16.824 9.491 ;
     RECT  21.936 9.299 21.96 9.685 ;
     RECT  4.032 6.805 4.056 10.019 ;
     RECT  16.416 9.491 16.44 10.069 ;
     RECT  14.688 7.907 15.144 10.213 ;
     RECT  16.272 10.069 16.44 10.213 ;
     RECT  23.616 7.667 24.312 10.261 ;
     RECT  36.72 6.229 36.744 10.307 ;
     RECT  2.304 8.195 2.712 10.355 ;
     RECT  7.8 8.963 13.512 10.453 ;
     RECT  14.688 10.213 16.44 10.453 ;
     RECT  34.176 8.869 35.112 10.501 ;
     RECT  33.648 10.501 35.112 10.547 ;
     RECT  7.8 10.453 16.44 10.741 ;
     RECT  5.376 6.899 5.4 10.789 ;
     RECT  5.376 10.789 5.592 10.835 ;
     RECT  34.8 10.547 35.112 11.269 ;
     RECT  7.152 10.741 16.44 11.509 ;
     RECT  18.6 9.013 20.04 11.509 ;
     RECT  38.784 10.837 38.808 11.651 ;
     RECT  7.152 11.509 16.632 11.699 ;
     RECT  33.648 10.547 33.672 11.843 ;
     RECT  18.6 11.509 20.52 12.035 ;
     RECT  18.6 12.035 18.912 12.085 ;
     RECT  18.48 12.085 18.912 12.469 ;
     RECT  7.8 11.699 13.512 12.709 ;
     RECT  23.328 10.261 24.312 12.755 ;
     RECT  29.4 7.955 30.12 12.805 ;
     RECT  6.864 12.709 13.512 12.853 ;
     RECT  21.888 9.685 21.96 12.899 ;
     RECT  29.4 12.805 30.792 12.947 ;
     RECT  18.24 12.469 18.912 13.045 ;
     RECT  20.016 12.035 20.52 13.045 ;
     RECT  40.2 5.171 40.512 13.045 ;
     RECT  5.568 10.835 5.592 13.139 ;
     RECT  18.24 13.045 20.52 13.139 ;
     RECT  18.24 13.139 20.04 13.379 ;
     RECT  34.8 11.269 35.736 13.573 ;
     RECT  18.48 13.379 20.04 13.715 ;
     RECT  14.688 11.699 16.632 13.861 ;
     RECT  24 12.755 24.312 13.909 ;
     RECT  37.2 12.901 37.224 14.003 ;
     RECT  6.864 12.853 13.656 14.197 ;
     RECT  14.688 13.861 17.448 14.197 ;
     RECT  6.864 14.197 17.448 14.243 ;
     RECT  16.608 14.243 17.448 14.435 ;
     RECT  34.608 13.573 35.736 14.485 ;
     RECT  6.864 14.243 14.904 14.819 ;
     RECT  17.424 14.435 17.448 14.867 ;
     RECT  20.352 14.197 20.376 14.867 ;
     RECT  21.888 12.899 21.912 14.867 ;
     RECT  27.264 11.845 27.288 14.917 ;
     RECT  26.736 14.917 27.288 14.963 ;
     RECT  34.128 14.485 35.736 15.203 ;
     RECT  34.128 15.203 35.112 15.443 ;
     RECT  39.312 13.045 40.512 15.443 ;
     RECT  22.896 14.773 22.92 15.491 ;
     RECT  18.48 13.715 19.08 15.779 ;
     RECT  16.848 15.733 16.872 15.877 ;
     RECT  18.48 15.779 18.912 15.923 ;
     RECT  29.4 12.947 30.504 15.925 ;
     RECT  4.992 13.573 5.016 16.019 ;
     RECT  7.152 14.819 14.904 16.019 ;
     RECT  24 13.909 24.552 16.019 ;
     RECT  28.464 15.925 30.504 16.019 ;
     RECT  7.8 16.019 14.904 16.067 ;
     RECT  15.936 15.877 16.872 16.259 ;
     RECT  9.408 16.067 14.904 16.307 ;
     RECT  18.6 15.923 18.912 17.077 ;
     RECT  40.2 15.443 40.512 17.077 ;
     RECT  32.352 14.821 32.376 17.123 ;
     RECT  7.8 16.067 8.376 17.461 ;
     RECT  9.408 16.307 13.512 17.461 ;
     RECT  14.688 16.307 14.904 17.461 ;
     RECT  15.936 16.259 15.96 17.461 ;
     RECT  2.4 10.355 2.712 17.605 ;
     RECT  24 16.019 24.312 17.605 ;
     RECT  7.8 17.461 13.512 17.891 ;
     RECT  26.736 14.963 26.76 18.181 ;
     RECT  26.208 18.181 26.76 18.227 ;
     RECT  39.936 17.077 40.512 18.227 ;
     RECT  23.328 17.605 24.312 18.419 ;
     RECT  2.4 17.605 2.808 18.661 ;
     RECT  4.896 17.653 4.92 18.707 ;
     RECT  36.624 18.661 36.648 18.757 ;
     RECT  22.608 18.421 22.632 18.851 ;
     RECT  26.208 18.227 26.232 18.851 ;
     RECT  18.6 17.077 19.368 18.853 ;
     RECT  14.688 17.461 15.96 18.995 ;
     RECT  34.8 15.443 35.112 19.045 ;
     RECT  36.576 18.757 36.648 19.283 ;
     RECT  2.4 18.661 3.672 19.475 ;
     RECT  18.6 18.853 19.896 19.861 ;
     RECT  7.8 17.891 8.664 19.909 ;
     RECT  18.48 19.861 19.896 19.909 ;
     RECT  17.712 19.909 19.896 19.955 ;
     RECT  10.128 17.891 13.512 20.533 ;
     RECT  27.456 19.477 27.48 20.579 ;
     RECT  34.8 19.045 35.352 20.579 ;
     RECT  28.464 16.019 29.712 20.627 ;
     RECT  36.576 19.283 36.6 20.725 ;
     RECT  36.576 20.725 36.744 20.771 ;
     RECT  7.68 19.909 8.664 20.821 ;
     RECT  9.696 20.533 13.512 20.821 ;
     RECT  30.816 19.909 30.84 20.915 ;
     RECT  17.712 19.955 19.416 21.155 ;
     RECT  7.44 20.821 13.512 21.251 ;
     RECT  29.04 20.627 29.712 21.395 ;
     RECT  2.4 19.475 3.432 21.635 ;
     RECT  7.68 21.251 13.512 21.683 ;
     RECT  2.4 21.635 2.712 22.165 ;
     RECT  4.464 21.109 4.488 22.451 ;
     RECT  21.36 17.365 21.384 22.645 ;
     RECT  7.68 21.683 8.76 22.741 ;
     RECT  10.128 21.683 13.512 22.741 ;
     RECT  17.712 21.155 19.176 22.741 ;
     RECT  36.72 20.771 36.744 22.741 ;
     RECT  26.208 21.637 26.232 22.835 ;
     RECT  2.304 22.165 2.712 23.411 ;
     RECT  7.68 22.741 13.512 23.843 ;
     RECT  36.72 22.741 37.608 23.843 ;
     RECT  39.12 19.333 39.144 23.843 ;
     RECT  7.68 23.843 8.76 23.939 ;
     RECT  34.8 20.579 35.112 23.989 ;
     RECT  17.616 22.741 19.176 24.469 ;
     RECT  34.704 23.989 35.112 24.515 ;
     RECT  5.424 22.741 5.448 24.659 ;
     RECT  36.72 23.843 37.08 24.899 ;
     RECT  17.328 24.469 19.176 25.139 ;
     RECT  2.4 23.411 2.712 25.237 ;
     RECT  36.72 24.899 36.744 25.237 ;
     RECT  26.208 24.229 26.232 25.283 ;
     RECT  2.4 25.237 2.808 25.429 ;
     RECT  7.8 23.939 8.76 25.715 ;
     RECT  23.904 18.419 24.312 25.763 ;
     RECT  14.688 18.995 15.672 25.811 ;
     RECT  7.8 25.715 8.568 26.053 ;
     RECT  36.576 25.237 36.744 26.101 ;
     RECT  2.4 25.429 2.856 26.291 ;
     RECT  17.424 25.139 18.912 26.725 ;
     RECT  20.736 22.645 21.384 26.771 ;
     RECT  36.576 26.101 37.08 26.819 ;
     RECT  7.44 26.053 8.568 27.107 ;
     RECT  2.4 26.291 2.808 27.347 ;
     RECT  7.44 27.107 8.112 27.395 ;
     RECT  36.576 26.819 36.6 27.395 ;
     RECT  40.2 18.227 40.512 27.877 ;
     RECT  17.328 26.725 18.912 27.923 ;
     RECT  14.688 25.811 14.712 27.925 ;
     RECT  14.688 27.925 15.192 28.309 ;
     RECT  20.832 26.771 21.384 28.453 ;
     RECT  24 25.763 24.312 28.453 ;
     RECT  7.584 27.395 8.112 28.789 ;
     RECT  2.4 27.347 2.712 28.933 ;
     RECT  4.32 28.405 4.344 28.933 ;
     RECT  2.4 28.933 4.344 28.979 ;
     RECT  24 28.453 25.176 29.027 ;
     RECT  6.048 26.437 6.072 29.123 ;
     RECT  17.328 27.923 17.352 29.123 ;
     RECT  38.976 25.333 39 29.123 ;
     RECT  2.4 28.979 3.432 29.795 ;
     RECT  18.6 27.923 18.912 30.037 ;
     RECT  20.256 28.453 21.384 30.037 ;
     RECT  18.6 30.037 21.384 30.181 ;
     RECT  34.8 24.515 35.112 30.229 ;
     RECT  18.384 30.181 21.576 30.275 ;
     RECT  0.24 14.869 0.264 30.419 ;
     RECT  29.4 21.395 29.712 30.709 ;
     RECT  40.08 27.877 40.512 30.949 ;
     RECT  10.128 23.843 13.512 31.189 ;
     RECT  28.8 30.709 29.712 31.283 ;
     RECT  18.384 30.275 20.28 31.379 ;
     RECT  34.8 30.229 35.208 31.379 ;
     RECT  9.696 31.189 13.512 31.717 ;
     RECT  7.584 28.789 8.28 32.003 ;
     RECT  7.8 32.003 8.28 32.243 ;
     RECT  9.696 31.717 13.608 32.531 ;
     RECT  10.8 32.531 13.608 32.771 ;
     RECT  21.36 30.275 21.576 32.771 ;
     RECT  39.84 30.949 40.512 33.013 ;
     RECT  14.688 28.309 15.24 33.155 ;
     RECT  5.184 30.469 5.208 33.589 ;
     RECT  7.8 32.243 8.112 33.637 ;
     RECT  9.696 32.531 9.72 33.683 ;
     RECT  10.8 32.771 13.512 33.683 ;
     RECT  18.6 31.379 20.28 33.683 ;
     RECT  5.088 33.589 5.208 33.827 ;
     RECT  7.8 33.637 8.52 33.877 ;
     RECT  11.376 33.683 13.512 33.923 ;
     RECT  7.68 33.877 8.52 34.117 ;
     RECT  24 29.027 24.312 34.165 ;
     RECT  36.528 32.869 36.552 34.355 ;
     RECT  5.088 33.827 5.112 34.501 ;
     RECT  7.68 34.117 9 34.741 ;
     RECT  23.712 34.165 24.312 34.741 ;
     RECT  34.8 31.379 35.112 34.741 ;
     RECT  11.808 33.923 13.512 34.789 ;
     RECT  15.216 33.155 15.24 34.835 ;
     RECT  6.912 34.741 9 34.931 ;
     RECT  2.4 29.795 2.712 35.029 ;
     RECT  23.712 34.741 24.888 35.315 ;
     RECT  39.312 33.013 40.512 35.411 ;
     RECT  34.8 34.741 35.208 35.605 ;
     RECT  2.4 35.029 3.24 35.939 ;
     RECT  11.808 34.789 14.232 35.939 ;
     RECT  4.32 34.501 5.112 35.987 ;
     RECT  23.904 35.315 24.888 35.987 ;
     RECT  6.912 34.931 8.904 36.227 ;
     RECT  29.4 31.283 29.712 36.325 ;
     RECT  7.68 36.227 8.904 36.515 ;
     RECT  18.6 33.683 19.752 36.515 ;
     RECT  23.904 35.987 24.408 36.515 ;
     RECT  27.84 35.941 27.864 36.755 ;
     RECT  34.8 35.605 35.688 36.997 ;
     RECT  39.36 35.411 40.512 37.091 ;
     RECT  4.32 35.987 4.344 37.189 ;
     RECT  11.808 35.939 13.608 37.283 ;
     RECT  15.456 35.845 15.48 37.619 ;
     RECT  11.808 37.283 13.512 37.955 ;
     RECT  4.32 37.189 4.632 38.005 ;
     RECT  24 36.515 24.408 38.149 ;
     RECT  34.56 36.997 35.688 38.149 ;
     RECT  29.4 36.325 30.504 38.389 ;
     RECT  7.68 36.515 8.112 38.435 ;
     RECT  10.752 37.573 10.776 38.435 ;
     RECT  12.192 37.955 13.512 38.485 ;
     RECT  34.176 38.149 35.688 38.581 ;
     RECT  28.656 38.389 30.504 38.675 ;
     RECT  38.784 37.573 38.808 38.677 ;
     RECT  39.936 37.091 40.512 38.677 ;
     RECT  20.208 37.573 20.232 38.771 ;
     RECT  38.784 38.677 40.512 38.915 ;
     RECT  3.744 38.005 4.632 38.963 ;
     RECT  21.36 32.771 21.384 39.301 ;
     RECT  12.192 38.485 14.28 39.347 ;
     RECT  38.784 38.915 38.808 39.779 ;
     RECT  31.824 39.637 31.848 39.877 ;
     RECT  9.552 39.061 9.576 39.923 ;
     RECT  34.176 38.581 36.12 40.019 ;
     RECT  12.192 39.347 13.512 40.163 ;
     RECT  39.936 38.915 40.512 40.405 ;
     RECT  4.32 38.963 4.344 40.453 ;
     RECT  4.32 40.453 4.584 40.499 ;
     RECT  24 38.149 25.224 40.547 ;
     RECT  20.4 39.301 21.384 40.595 ;
     RECT  12.192 40.163 12.216 40.741 ;
     RECT  13.2 40.163 13.512 40.981 ;
     RECT  34.176 40.019 35.688 40.981 ;
     RECT  28.656 38.675 29.712 41.075 ;
     RECT  34.176 40.981 35.832 41.075 ;
     RECT  39.264 40.405 40.512 41.075 ;
     RECT  29.4 41.075 29.712 41.557 ;
     RECT  31.68 39.877 31.848 41.651 ;
     RECT  37.056 40.405 37.08 41.651 ;
     RECT  11.712 40.741 12.216 41.749 ;
     RECT  21.36 40.595 21.384 41.749 ;
     RECT  21.12 41.749 21.384 41.795 ;
     RECT  24 40.547 24.408 41.891 ;
     RECT  31.728 41.651 31.848 42.133 ;
     RECT  16.56 39.301 16.584 42.179 ;
     RECT  21.12 41.795 21.144 42.179 ;
     RECT  28.368 41.845 28.392 42.323 ;
     RECT  13.2 40.981 14.28 42.755 ;
     RECT  4.56 40.499 4.584 42.803 ;
     RECT  29.4 41.557 30.408 42.803 ;
     RECT  2.4 35.939 2.712 43.285 ;
     RECT  11.424 41.749 12.216 43.331 ;
     RECT  11.424 43.331 11.736 43.523 ;
     RECT  25.632 42.709 25.656 43.571 ;
     RECT  13.2 42.755 13.512 44.053 ;
     RECT  27.36 42.133 27.384 44.245 ;
     RECT  7.8 38.435 8.112 44.341 ;
     RECT  24 41.891 24.312 44.341 ;
     RECT  24 44.341 24.696 44.389 ;
     RECT  5.52 43.429 5.544 44.437 ;
     RECT  11.424 43.523 11.448 44.483 ;
     RECT  31.728 42.133 32.088 44.483 ;
     RECT  32.064 44.483 32.088 44.531 ;
     RECT  2.304 43.285 2.712 44.579 ;
     RECT  23.616 44.389 24.696 44.773 ;
     RECT  5.088 44.437 6.312 45.059 ;
     RECT  27.36 44.245 28.008 45.059 ;
     RECT  12.96 44.053 13.512 45.155 ;
     RECT  27.984 45.059 28.008 45.299 ;
     RECT  13.2 45.155 13.512 45.301 ;
     RECT  5.088 45.059 5.112 45.395 ;
     RECT  11.952 44.965 11.976 45.541 ;
     RECT  6.288 45.059 6.312 45.587 ;
     RECT  22.752 44.773 24.696 45.587 ;
     RECT  34.608 41.075 35.832 45.635 ;
     RECT  15.936 44.437 15.96 45.637 ;
     RECT  15.456 45.637 15.96 45.683 ;
     RECT  13.2 45.301 14.04 46.115 ;
     RECT  34.608 45.635 35.112 46.117 ;
     RECT  15.456 45.683 15.48 46.499 ;
     RECT  7.632 44.341 8.112 46.501 ;
     RECT  11.808 45.541 11.976 46.835 ;
     RECT  7.392 46.501 8.112 47.315 ;
     RECT  39.888 41.075 40.512 47.411 ;
     RECT  2.4 44.579 2.712 47.557 ;
     RECT  5.088 46.645 5.112 47.603 ;
     RECT  38.016 47.269 38.04 47.845 ;
     RECT  11.952 46.835 11.976 47.891 ;
     RECT  25.68 46.069 25.704 47.939 ;
     RECT  23.904 45.587 24.696 48.085 ;
     RECT  34.56 46.117 35.112 48.325 ;
     RECT  18.6 36.515 18.912 48.373 ;
     RECT  15.6 47.173 15.624 48.419 ;
     RECT  7.8 47.315 8.112 48.421 ;
     RECT  38.016 47.845 39 48.467 ;
     RECT  10.704 47.221 10.728 48.949 ;
     RECT  40.2 47.411 40.512 48.949 ;
     RECT  7.8 48.421 8.472 48.997 ;
     RECT  6.288 48.277 6.312 49.043 ;
     RECT  18.6 48.373 19.416 49.043 ;
     RECT  7.8 48.997 9.144 49.139 ;
     RECT  2.4 47.557 2.904 49.187 ;
     RECT  32.112 48.949 32.136 49.235 ;
     RECT  7.8 49.139 8.472 49.333 ;
     RECT  10.704 48.949 10.872 49.379 ;
     RECT  34.224 48.325 35.112 49.379 ;
     RECT  13.2 46.115 13.512 49.477 ;
     RECT  34.8 49.379 35.112 49.861 ;
     RECT  18.6 49.043 18.912 50.005 ;
     RECT  7.68 49.333 8.472 50.101 ;
     RECT  13.2 49.477 13.608 50.389 ;
     RECT  15.36 48.997 15.384 50.627 ;
     RECT  34.8 49.861 35.928 50.723 ;
     RECT  39.312 48.949 40.512 50.723 ;
     RECT  7.68 50.101 9 50.771 ;
     RECT  18.6 50.005 19.032 50.771 ;
     RECT  13.104 50.389 13.608 50.867 ;
     RECT  11.952 49.813 11.976 50.963 ;
     RECT  23.424 48.085 24.696 51.205 ;
     RECT  34.8 50.723 35.112 51.253 ;
     RECT  13.2 50.867 13.608 51.397 ;
     RECT  10.704 49.379 10.728 51.541 ;
     RECT  13.2 51.397 13.656 51.685 ;
     RECT  13.2 51.685 13.752 51.733 ;
     RECT  7.8 50.771 9 51.781 ;
     RECT  10.512 51.541 10.728 51.781 ;
     RECT  7.8 51.781 9.528 51.829 ;
     RECT  10.512 51.781 11.832 51.829 ;
     RECT  17.28 51.253 17.304 51.875 ;
     RECT  13.2 51.733 14.376 51.925 ;
     RECT  36.864 51.253 36.888 52.021 ;
     RECT  38.016 48.467 38.04 52.021 ;
     RECT  36.48 52.021 36.888 52.067 ;
     RECT  23.328 51.205 24.696 52.211 ;
     RECT  23.328 52.211 24.312 52.595 ;
     RECT  34.704 51.253 35.112 52.645 ;
     RECT  13.008 51.925 14.376 52.837 ;
     RECT  4.464 48.997 4.488 52.981 ;
     RECT  36.48 52.067 36.504 53.075 ;
     RECT  28.272 48.949 28.296 53.219 ;
     RECT  7.8 51.829 11.832 53.555 ;
     RECT  29.4 42.803 29.712 53.557 ;
     RECT  7.8 53.555 10.632 53.603 ;
     RECT  23.424 52.595 24.312 53.797 ;
     RECT  34.368 52.645 35.112 53.797 ;
     RECT  22.848 53.797 24.312 53.843 ;
     RECT  11.808 53.555 11.832 53.893 ;
     RECT  12.912 52.837 14.376 53.893 ;
     RECT  4.464 52.981 4.824 54.371 ;
     RECT  38.016 52.021 38.232 54.563 ;
     RECT  4.464 54.371 4.488 54.565 ;
     RECT  4.224 54.565 4.488 54.611 ;
     RECT  38.16 54.563 38.232 54.755 ;
     RECT  7.8 53.603 10.536 55.141 ;
     RECT  11.808 53.893 14.376 55.141 ;
     RECT  7.8 55.141 14.376 55.237 ;
     RECT  22.848 53.843 22.872 55.237 ;
     RECT  22.752 55.237 22.872 55.283 ;
     RECT  28.464 53.557 29.712 55.715 ;
     RECT  4.224 54.611 4.248 55.907 ;
     RECT  17.28 55.381 17.304 55.955 ;
     RECT  7.392 55.237 14.376 56.051 ;
     RECT  38.16 54.755 38.184 56.435 ;
     RECT  7.392 56.051 13.752 56.483 ;
     RECT  22.752 55.283 22.776 56.483 ;
     RECT  34.224 53.797 35.112 57.011 ;
     RECT  7.392 56.483 13.608 57.059 ;
     RECT  7.392 57.059 13.512 57.635 ;
     RECT  34.656 57.011 35.112 57.635 ;
     RECT  7.8 57.635 11.064 58.019 ;
     RECT  2.4 49.187 2.712 58.329 ;
     RECT  7.8 58.019 8.112 58.329 ;
     RECT  13.2 57.635 13.512 58.329 ;
     RECT  18.6 50.771 18.912 58.329 ;
     RECT  24 53.843 24.312 58.329 ;
     RECT  29.4 55.715 29.712 58.329 ;
     RECT  34.8 57.635 35.112 58.329 ;
     RECT  40.2 50.723 40.512 58.329 ;
     RECT  2.4 58.329 2.52 58.343 ;
     RECT  7.8 58.329 7.92 58.343 ;
     RECT  13.2 58.329 13.32 58.343 ;
     RECT  18.6 58.329 18.72 58.343 ;
     RECT  24 58.329 24.12 58.343 ;
     RECT  29.4 58.329 29.52 58.343 ;
     RECT  34.8 58.329 34.92 58.343 ;
     RECT  40.2 58.329 40.32 58.343 ;
     RECT  9.12 58.019 11.064 58.645 ;
     RECT  9.12 58.645 11.208 59.269 ;
     RECT  9.024 59.269 11.208 60.304 ;
     RECT  4.152 2.821 5.184 2.963 ;
     RECT  3.624 2.963 5.184 3.109 ;
     RECT  5.208 3.061 6.336 3.877 ;
     RECT  3.624 3.109 5.136 4.019 ;
     RECT  15.384 3.349 16.848 3.539 ;
     RECT  16.872 3.395 17.064 4.645 ;
     RECT  18.912 3.635 19.32 5.029 ;
     RECT  22.056 3.877 23.184 5.459 ;
     RECT  24.552 3.925 25.968 5.747 ;
     RECT  10.176 4.019 10.704 4.501 ;
     RECT  5.376 4.115 5.424 5.173 ;
     RECT  8.112 4.501 9.408 4.645 ;
     RECT  9.432 4.501 10.704 5.173 ;
     RECT  8.232 4.645 9.408 5.029 ;
     RECT  17.112 4.645 18.6 5.171 ;
     RECT  5.88 5.027 7.2 6.899 ;
     RECT  8.28 5.029 9.408 5.989 ;
     RECT  16.872 5.171 18.6 5.701 ;
     RECT  9.432 5.173 10.416 6.709 ;
     RECT  22.056 5.459 24 6.805 ;
     RECT  2.712 5.507 3.624 6.805 ;
     RECT  16.872 5.701 18.24 6.323 ;
     RECT  8.328 5.989 9.408 6.085 ;
     RECT  8.376 6.085 9.408 7.285 ;
     RECT  35.736 6.229 36.72 6.899 ;
     RECT  15.096 6.323 15.144 6.371 ;
     RECT  15 6.371 15.144 7.381 ;
     RECT  2.712 6.805 4.032 7.813 ;
     RECT  4.056 6.805 5.376 10.019 ;
     RECT  22.632 6.805 24 7.621 ;
     RECT  38.808 6.853 40.2 7.475 ;
     RECT  5.4 6.899 7.2 7.045 ;
     RECT  5.4 7.045 6.768 7.427 ;
     RECT  38.784 7.475 40.2 8.437 ;
     RECT  22.632 7.621 23.616 9.251 ;
     RECT  2.856 7.813 4.032 7.909 ;
     RECT  15.144 7.861 16.416 10.069 ;
     RECT  13.608 7.907 14.688 8.003 ;
     RECT  2.952 7.909 4.032 8.195 ;
     RECT  13.512 8.003 14.688 10.453 ;
     RECT  2.712 8.195 4.032 10.019 ;
     RECT  38.808 8.437 40.2 9.155 ;
     RECT  22.056 9.251 23.616 9.299 ;
     RECT  21.96 9.299 23.616 10.261 ;
     RECT  15.144 10.069 16.272 10.213 ;
     RECT  21.96 10.261 23.328 12.755 ;
     RECT  33.672 10.547 34.8 11.843 ;
     RECT  38.808 10.837 40.2 11.651 ;
     RECT  20.52 11.509 21.888 13.139 ;
     RECT  39.312 11.651 40.2 13.045 ;
     RECT  7.152 11.699 7.8 12.709 ;
     RECT  13.512 11.699 14.688 12.853 ;
     RECT  18.912 12.035 20.016 13.045 ;
     RECT  5.592 12.709 6.864 13.139 ;
     RECT  13.656 12.853 14.688 14.197 ;
     RECT  35.736 12.901 37.2 14.003 ;
     RECT  20.04 13.139 21.888 13.715 ;
     RECT  18.24 13.379 18.48 13.861 ;
     RECT  19.08 13.715 21.888 14.197 ;
     RECT  17.448 13.861 18.48 14.867 ;
     RECT  19.08 14.197 20.352 14.867 ;
     RECT  20.376 14.197 21.888 14.867 ;
     RECT  16.608 14.435 17.424 14.867 ;
     RECT  21.912 14.773 22.896 14.867 ;
     RECT  22.92 14.773 24 15.491 ;
     RECT  16.608 14.867 16.872 15.733 ;
     RECT  16.608 15.733 16.848 15.877 ;
     RECT  18.912 15.779 19.08 17.077 ;
     RECT  14.904 15.877 15.936 17.461 ;
     RECT  8.376 16.067 9.408 17.461 ;
     RECT  13.512 16.307 14.688 31.717 ;
     RECT  8.664 17.891 10.128 20.533 ;
     RECT  39.936 18.227 40.2 19.333 ;
     RECT  23.328 18.419 23.904 18.421 ;
     RECT  21.384 18.421 22.608 18.851 ;
     RECT  22.632 18.421 23.904 18.851 ;
     RECT  3.672 18.661 4.896 18.707 ;
     RECT  35.112 18.661 36.624 18.757 ;
     RECT  35.112 18.757 36.576 19.045 ;
     RECT  19.896 18.853 21.36 19.955 ;
     RECT  35.352 19.045 36.576 20.579 ;
     RECT  36.6 19.283 36.648 20.725 ;
     RECT  39.144 19.333 40.2 23.843 ;
     RECT  27.48 19.477 28.464 20.579 ;
     RECT  29.712 19.909 30.816 20.915 ;
     RECT  8.664 20.533 9.696 20.821 ;
     RECT  35.112 20.579 36.576 20.771 ;
     RECT  3.432 21.109 4.464 21.635 ;
     RECT  8.76 21.683 10.128 22.741 ;
     RECT  37.608 22.741 39.12 23.843 ;
     RECT  26.208 22.835 26.232 24.229 ;
     RECT  8.76 23.843 10.128 25.715 ;
     RECT  38.976 23.843 40.2 25.333 ;
     RECT  36.744 24.899 37.08 26.101 ;
     RECT  35.112 25.237 36.576 27.395 ;
     RECT  39 25.333 40.2 27.877 ;
     RECT  6.072 26.437 7.44 27.395 ;
     RECT  6.072 27.395 7.584 29.123 ;
     RECT  39 27.877 40.08 29.123 ;
     RECT  17.352 27.923 18.6 29.123 ;
     RECT  18.912 28.453 20.256 30.037 ;
     RECT  18.384 29.123 18.6 30.181 ;
     RECT  20.28 30.275 21.36 33.683 ;
     RECT  8.28 31.189 9.696 32.243 ;
     RECT  35.112 31.379 35.208 32.869 ;
     RECT  13.608 31.717 14.688 32.771 ;
     RECT  8.112 32.243 9.696 33.637 ;
     RECT  9.72 32.531 10.8 33.683 ;
     RECT  13.512 32.771 14.688 33.155 ;
     RECT  35.112 32.869 36.528 34.355 ;
     RECT  8.52 33.637 9.696 33.683 ;
     RECT  8.52 33.683 9 34.117 ;
     RECT  35.112 34.355 35.688 34.741 ;
     RECT  35.208 34.741 35.688 35.605 ;
     RECT  14.232 34.789 15.216 34.835 ;
     RECT  14.232 34.835 15.24 35.845 ;
     RECT  3.24 35.029 4.32 35.939 ;
     RECT  14.232 35.845 15.456 35.939 ;
     RECT  4.344 35.987 4.632 37.189 ;
     RECT  18.912 36.515 19.752 37.573 ;
     RECT  39.36 37.091 39.936 37.573 ;
     RECT  13.512 37.283 13.608 38.485 ;
     RECT  10.776 37.573 11.808 37.955 ;
     RECT  18.912 37.573 20.208 38.771 ;
     RECT  20.232 37.573 21.36 38.771 ;
     RECT  38.808 37.573 39.936 38.677 ;
     RECT  10.776 37.955 12.192 38.435 ;
     RECT  2.712 38.005 3.744 38.963 ;
     RECT  18.912 38.771 21.36 39.301 ;
     RECT  38.808 38.915 39.936 39.779 ;
     RECT  4.344 38.963 4.584 40.453 ;
     RECT  8.112 39.061 9.552 39.923 ;
     RECT  18.912 39.301 20.4 40.595 ;
     RECT  39.264 39.779 39.936 40.405 ;
     RECT  35.688 40.019 36.12 40.405 ;
     RECT  12.216 40.163 13.2 43.331 ;
     RECT  35.688 40.405 37.056 40.981 ;
     RECT  21.12 40.595 21.36 41.749 ;
     RECT  35.832 40.981 37.056 41.651 ;
     RECT  28.656 41.075 29.4 41.845 ;
     RECT  30.408 41.557 31.68 41.651 ;
     RECT  30.408 41.651 31.728 42.803 ;
     RECT  28.392 41.845 29.4 42.323 ;
     RECT  24.312 41.891 24.408 42.709 ;
     RECT  27.384 42.133 28.368 42.323 ;
     RECT  24.312 42.709 25.632 43.571 ;
     RECT  11.736 43.331 13.2 43.523 ;
     RECT  11.448 43.523 13.2 44.053 ;
     RECT  24.312 43.571 24.696 44.341 ;
     RECT  11.448 44.053 12.96 44.483 ;
     RECT  28.008 44.245 29.4 45.299 ;
     RECT  6.312 44.437 7.632 45.587 ;
     RECT  11.808 44.483 12.96 44.965 ;
     RECT  11.808 44.965 11.952 45.541 ;
     RECT  11.976 44.965 12.96 45.155 ;
     RECT  5.112 45.059 6.288 45.395 ;
     RECT  11.976 45.155 13.2 47.891 ;
     RECT  5.088 45.395 6.288 45.587 ;
     RECT  5.088 45.587 5.112 46.645 ;
     RECT  7.392 45.587 7.632 46.501 ;
     RECT  14.04 45.637 15.456 46.115 ;
     RECT  15.48 45.683 15.624 46.499 ;
     RECT  24.696 46.069 25.68 47.939 ;
     RECT  15.6 46.499 15.624 47.173 ;
     RECT  11.808 46.835 11.952 47.221 ;
     RECT  10.728 47.221 11.952 47.891 ;
     RECT  7.392 47.315 7.8 48.277 ;
     RECT  39.888 47.411 40.2 47.845 ;
     RECT  39 47.845 40.2 48.467 ;
     RECT  10.728 47.891 10.872 48.949 ;
     RECT  6.312 48.277 7.8 49.043 ;
     RECT  38.04 48.467 40.2 48.949 ;
     RECT  28.296 48.949 29.4 53.219 ;
     RECT  38.04 48.949 39.312 50.723 ;
     RECT  7.68 49.043 7.8 49.333 ;
     RECT  18.912 49.043 19.032 50.005 ;
     RECT  8.472 49.139 9 50.101 ;
     RECT  10.728 49.379 10.872 49.813 ;
     RECT  10.728 49.813 11.952 50.963 ;
     RECT  11.976 49.813 13.2 50.389 ;
     RECT  11.976 50.389 13.104 50.867 ;
     RECT  35.112 50.723 35.928 51.253 ;
     RECT  38.04 50.723 38.232 52.021 ;
     RECT  11.976 50.867 13.2 50.963 ;
     RECT  10.728 50.963 13.2 51.781 ;
     RECT  17.304 51.253 18.6 51.875 ;
     RECT  35.112 51.253 36.864 52.021 ;
     RECT  36.888 51.253 38.016 52.067 ;
     RECT  9 51.541 10.512 51.781 ;
     RECT  9.528 51.781 10.512 51.829 ;
     RECT  11.832 51.781 13.2 51.925 ;
     RECT  11.832 51.925 13.008 52.837 ;
     RECT  35.112 52.021 36.48 53.075 ;
     RECT  36.504 52.067 38.016 53.075 ;
     RECT  23.328 52.595 23.424 53.797 ;
     RECT  11.832 52.837 12.912 53.893 ;
     RECT  28.464 53.219 29.4 53.557 ;
     RECT  10.632 53.555 11.808 53.603 ;
     RECT  10.536 53.603 11.808 55.141 ;
     RECT  22.872 53.843 24 55.283 ;
     RECT  2.712 54.565 4.224 55.907 ;
     RECT  22.776 55.283 24 56.483 ;
     RECT  17.304 55.381 18.6 55.955 ;
     RECT  11.064 57.635 11.208 58.645 ;
     RECT  8.112 58.019 9.12 58.329 ;
     RECT  7.92 58.329 9.12 58.343 ;
     RECT  9.024 58.343 9.12 59.269 ;
  END
END ot_s81_markov_chunk2_native
END LIBRARY
